VERSION 5.8 ;
BUSBITCHARS "[]" ;
DIVIDERCHAR "/" ;
UNITS
    DATABASE MICRONS 1000 ;
END UNITS

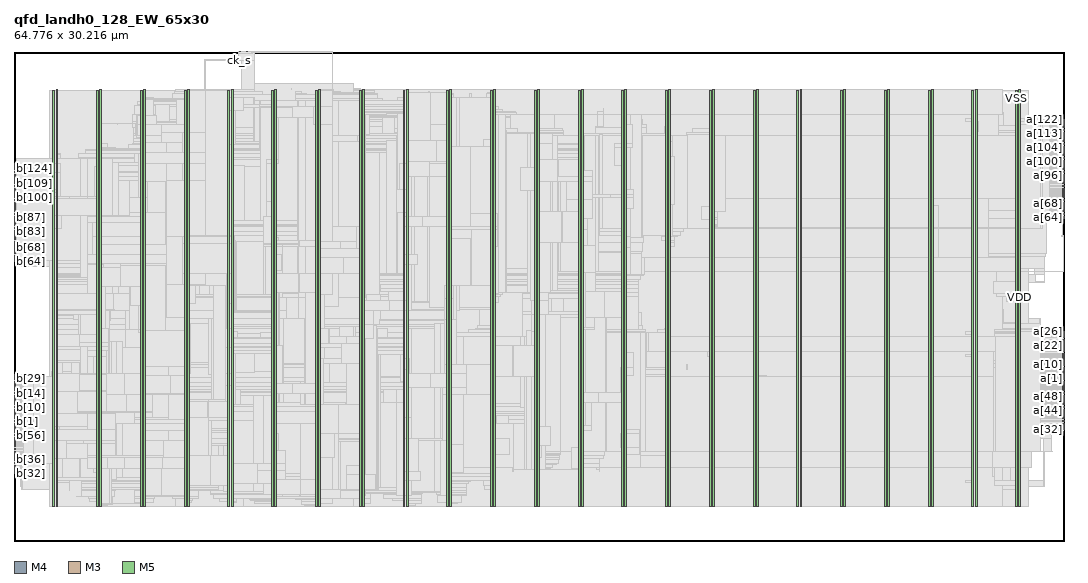
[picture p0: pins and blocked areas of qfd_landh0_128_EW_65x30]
MACRO qfd_landh0_128_EW_65x30
  FOREIGN qfd_landh0_128_EW_65x30 0 0 ;
  CLASS BLOCK ;
  SIZE 64.776 BY 30.216 ;
  PIN a[0]
    DIRECTION INPUT ;
    USE SIGNAL ;
    PORT
      LAYER M4 ;
        RECT  64.692 9.936 64.776 9.96 ;
    END
  END a[0]
  PIN a[100]
    DIRECTION INPUT ;
    USE SIGNAL ;
    PORT
      LAYER M4 ;
        RECT  64.692 23.376 64.776 23.4 ;
    END
  END a[100]
  PIN a[101]
    DIRECTION INPUT ;
    USE SIGNAL ;
    PORT
      LAYER M4 ;
        RECT  64.692 23.472 64.776 23.496 ;
    END
  END a[101]
  PIN a[102]
    DIRECTION INPUT ;
    USE SIGNAL ;
    PORT
      LAYER M4 ;
        RECT  64.692 23.568 64.776 23.592 ;
    END
  END a[102]
  PIN a[103]
    DIRECTION INPUT ;
    USE SIGNAL ;
    PORT
      LAYER M4 ;
        RECT  64.692 23.664 64.776 23.688 ;
    END
  END a[103]
  PIN a[104]
    DIRECTION INPUT ;
    USE SIGNAL ;
    PORT
      LAYER M4 ;
        RECT  64.692 23.76 64.776 23.784 ;
    END
  END a[104]
  PIN a[105]
    DIRECTION INPUT ;
    USE SIGNAL ;
    PORT
      LAYER M4 ;
        RECT  64.692 23.856 64.776 23.88 ;
    END
  END a[105]
  PIN a[106]
    DIRECTION INPUT ;
    USE SIGNAL ;
    PORT
      LAYER M4 ;
        RECT  64.692 23.952 64.776 23.976 ;
    END
  END a[106]
  PIN a[107]
    DIRECTION INPUT ;
    USE SIGNAL ;
    PORT
      LAYER M4 ;
        RECT  64.692 24.048 64.776 24.072 ;
    END
  END a[107]
  PIN a[108]
    DIRECTION INPUT ;
    USE SIGNAL ;
    PORT
      LAYER M4 ;
        RECT  64.692 24.144 64.776 24.168 ;
    END
  END a[108]
  PIN a[109]
    DIRECTION INPUT ;
    USE SIGNAL ;
    PORT
      LAYER M4 ;
        RECT  64.692 24.24 64.776 24.264 ;
    END
  END a[109]
  PIN a[10]
    DIRECTION INPUT ;
    USE SIGNAL ;
    PORT
      LAYER M4 ;
        RECT  64.692 10.896 64.776 10.92 ;
    END
  END a[10]
  PIN a[110]
    DIRECTION INPUT ;
    USE SIGNAL ;
    PORT
      LAYER M4 ;
        RECT  64.692 24.336 64.776 24.36 ;
    END
  END a[110]
  PIN a[111]
    DIRECTION INPUT ;
    USE SIGNAL ;
    PORT
      LAYER M4 ;
        RECT  64.692 24.432 64.776 24.456 ;
    END
  END a[111]
  PIN a[112]
    DIRECTION INPUT ;
    USE SIGNAL ;
    PORT
      LAYER M4 ;
        RECT  64.692 24.528 64.776 24.552 ;
    END
  END a[112]
  PIN a[113]
    DIRECTION INPUT ;
    USE SIGNAL ;
    PORT
      LAYER M4 ;
        RECT  64.692 24.624 64.776 24.648 ;
    END
  END a[113]
  PIN a[114]
    DIRECTION INPUT ;
    USE SIGNAL ;
    PORT
      LAYER M4 ;
        RECT  64.692 24.72 64.776 24.744 ;
    END
  END a[114]
  PIN a[115]
    DIRECTION INPUT ;
    USE SIGNAL ;
    PORT
      LAYER M4 ;
        RECT  64.692 24.816 64.776 24.84 ;
    END
  END a[115]
  PIN a[116]
    DIRECTION INPUT ;
    USE SIGNAL ;
    PORT
      LAYER M4 ;
        RECT  64.692 24.912 64.776 24.936 ;
    END
  END a[116]
  PIN a[117]
    DIRECTION INPUT ;
    USE SIGNAL ;
    PORT
      LAYER M4 ;
        RECT  64.692 25.008 64.776 25.032 ;
    END
  END a[117]
  PIN a[118]
    DIRECTION INPUT ;
    USE SIGNAL ;
    PORT
      LAYER M4 ;
        RECT  64.692 25.104 64.776 25.128 ;
    END
  END a[118]
  PIN a[119]
    DIRECTION INPUT ;
    USE SIGNAL ;
    PORT
      LAYER M4 ;
        RECT  64.692 25.2 64.776 25.224 ;
    END
  END a[119]
  PIN a[11]
    DIRECTION INPUT ;
    USE SIGNAL ;
    PORT
      LAYER M4 ;
        RECT  64.692 10.992 64.776 11.016 ;
    END
  END a[11]
  PIN a[120]
    DIRECTION INPUT ;
    USE SIGNAL ;
    PORT
      LAYER M4 ;
        RECT  64.692 25.296 64.776 25.32 ;
    END
  END a[120]
  PIN a[121]
    DIRECTION INPUT ;
    USE SIGNAL ;
    PORT
      LAYER M4 ;
        RECT  64.692 25.392 64.776 25.416 ;
    END
  END a[121]
  PIN a[122]
    DIRECTION INPUT ;
    USE SIGNAL ;
    PORT
      LAYER M4 ;
        RECT  64.692 25.488 64.776 25.512 ;
    END
  END a[122]
  PIN a[123]
    DIRECTION INPUT ;
    USE SIGNAL ;
    PORT
      LAYER M4 ;
        RECT  64.692 25.584 64.776 25.608 ;
    END
  END a[123]
  PIN a[124]
    DIRECTION INPUT ;
    USE SIGNAL ;
    PORT
      LAYER M4 ;
        RECT  64.692 25.68 64.776 25.704 ;
    END
  END a[124]
  PIN a[125]
    DIRECTION INPUT ;
    USE SIGNAL ;
    PORT
      LAYER M4 ;
        RECT  64.692 25.776 64.776 25.8 ;
    END
  END a[125]
  PIN a[126]
    DIRECTION INPUT ;
    USE SIGNAL ;
    PORT
      LAYER M4 ;
        RECT  64.692 25.872 64.776 25.896 ;
    END
  END a[126]
  PIN a[127]
    DIRECTION INPUT ;
    USE SIGNAL ;
    PORT
      LAYER M4 ;
        RECT  64.692 25.968 64.776 25.992 ;
    END
  END a[127]
  PIN a[12]
    DIRECTION INPUT ;
    USE SIGNAL ;
    PORT
      LAYER M4 ;
        RECT  64.692 11.088 64.776 11.112 ;
    END
  END a[12]
  PIN a[13]
    DIRECTION INPUT ;
    USE SIGNAL ;
    PORT
      LAYER M4 ;
        RECT  64.692 11.184 64.776 11.208 ;
    END
  END a[13]
  PIN a[14]
    DIRECTION INPUT ;
    USE SIGNAL ;
    PORT
      LAYER M4 ;
        RECT  64.692 11.28 64.776 11.304 ;
    END
  END a[14]
  PIN a[15]
    DIRECTION INPUT ;
    USE SIGNAL ;
    PORT
      LAYER M4 ;
        RECT  64.692 11.376 64.776 11.4 ;
    END
  END a[15]
  PIN a[16]
    DIRECTION INPUT ;
    USE SIGNAL ;
    PORT
      LAYER M4 ;
        RECT  64.692 11.472 64.776 11.496 ;
    END
  END a[16]
  PIN a[17]
    DIRECTION INPUT ;
    USE SIGNAL ;
    PORT
      LAYER M4 ;
        RECT  64.692 11.568 64.776 11.592 ;
    END
  END a[17]
  PIN a[18]
    DIRECTION INPUT ;
    USE SIGNAL ;
    PORT
      LAYER M4 ;
        RECT  64.692 11.664 64.776 11.688 ;
    END
  END a[18]
  PIN a[19]
    DIRECTION INPUT ;
    USE SIGNAL ;
    PORT
      LAYER M4 ;
        RECT  64.692 11.76 64.776 11.784 ;
    END
  END a[19]
  PIN a[1]
    DIRECTION INPUT ;
    USE SIGNAL ;
    PORT
      LAYER M4 ;
        RECT  64.692 10.032 64.776 10.056 ;
    END
  END a[1]
  PIN a[20]
    DIRECTION INPUT ;
    USE SIGNAL ;
    PORT
      LAYER M4 ;
        RECT  64.692 11.856 64.776 11.88 ;
    END
  END a[20]
  PIN a[21]
    DIRECTION INPUT ;
    USE SIGNAL ;
    PORT
      LAYER M4 ;
        RECT  64.692 11.952 64.776 11.976 ;
    END
  END a[21]
  PIN a[22]
    DIRECTION INPUT ;
    USE SIGNAL ;
    PORT
      LAYER M4 ;
        RECT  64.692 12.048 64.776 12.072 ;
    END
  END a[22]
  PIN a[23]
    DIRECTION INPUT ;
    USE SIGNAL ;
    PORT
      LAYER M4 ;
        RECT  64.692 12.144 64.776 12.168 ;
    END
  END a[23]
  PIN a[24]
    DIRECTION INPUT ;
    USE SIGNAL ;
    PORT
      LAYER M4 ;
        RECT  64.692 12.24 64.776 12.264 ;
    END
  END a[24]
  PIN a[25]
    DIRECTION INPUT ;
    USE SIGNAL ;
    PORT
      LAYER M4 ;
        RECT  64.692 12.336 64.776 12.36 ;
    END
  END a[25]
  PIN a[26]
    DIRECTION INPUT ;
    USE SIGNAL ;
    PORT
      LAYER M4 ;
        RECT  64.692 12.432 64.776 12.456 ;
    END
  END a[26]
  PIN a[27]
    DIRECTION INPUT ;
    USE SIGNAL ;
    PORT
      LAYER M4 ;
        RECT  64.692 12.528 64.776 12.552 ;
    END
  END a[27]
  PIN a[28]
    DIRECTION INPUT ;
    USE SIGNAL ;
    PORT
      LAYER M4 ;
        RECT  64.692 12.624 64.776 12.648 ;
    END
  END a[28]
  PIN a[29]
    DIRECTION INPUT ;
    USE SIGNAL ;
    PORT
      LAYER M4 ;
        RECT  64.692 12.72 64.776 12.744 ;
    END
  END a[29]
  PIN a[2]
    DIRECTION INPUT ;
    USE SIGNAL ;
    PORT
      LAYER M4 ;
        RECT  64.692 10.128 64.776 10.152 ;
    END
  END a[2]
  PIN a[30]
    DIRECTION INPUT ;
    USE SIGNAL ;
    PORT
      LAYER M4 ;
        RECT  64.692 12.816 64.776 12.84 ;
    END
  END a[30]
  PIN a[31]
    DIRECTION INPUT ;
    USE SIGNAL ;
    PORT
      LAYER M4 ;
        RECT  64.692 12.912 64.776 12.936 ;
    END
  END a[31]
  PIN a[32]
    DIRECTION INPUT ;
    USE SIGNAL ;
    PORT
      LAYER M4 ;
        RECT  64.692 6.864 64.776 6.888 ;
    END
  END a[32]
  PIN a[33]
    DIRECTION INPUT ;
    USE SIGNAL ;
    PORT
      LAYER M4 ;
        RECT  64.692 6.96 64.776 6.984 ;
    END
  END a[33]
  PIN a[34]
    DIRECTION INPUT ;
    USE SIGNAL ;
    PORT
      LAYER M4 ;
        RECT  64.692 7.056 64.776 7.08 ;
    END
  END a[34]
  PIN a[35]
    DIRECTION INPUT ;
    USE SIGNAL ;
    PORT
      LAYER M4 ;
        RECT  64.692 7.152 64.776 7.176 ;
    END
  END a[35]
  PIN a[36]
    DIRECTION INPUT ;
    USE SIGNAL ;
    PORT
      LAYER M4 ;
        RECT  64.692 7.248 64.776 7.272 ;
    END
  END a[36]
  PIN a[37]
    DIRECTION INPUT ;
    USE SIGNAL ;
    PORT
      LAYER M4 ;
        RECT  64.692 7.344 64.776 7.368 ;
    END
  END a[37]
  PIN a[38]
    DIRECTION INPUT ;
    USE SIGNAL ;
    PORT
      LAYER M4 ;
        RECT  64.692 7.44 64.776 7.464 ;
    END
  END a[38]
  PIN a[39]
    DIRECTION INPUT ;
    USE SIGNAL ;
    PORT
      LAYER M4 ;
        RECT  64.692 7.536 64.776 7.56 ;
    END
  END a[39]
  PIN a[3]
    DIRECTION INPUT ;
    USE SIGNAL ;
    PORT
      LAYER M4 ;
        RECT  64.692 10.224 64.776 10.248 ;
    END
  END a[3]
  PIN a[40]
    DIRECTION INPUT ;
    USE SIGNAL ;
    PORT
      LAYER M4 ;
        RECT  64.692 7.632 64.776 7.656 ;
    END
  END a[40]
  PIN a[41]
    DIRECTION INPUT ;
    USE SIGNAL ;
    PORT
      LAYER M4 ;
        RECT  64.692 7.728 64.776 7.752 ;
    END
  END a[41]
  PIN a[42]
    DIRECTION INPUT ;
    USE SIGNAL ;
    PORT
      LAYER M4 ;
        RECT  64.692 7.824 64.776 7.848 ;
    END
  END a[42]
  PIN a[43]
    DIRECTION INPUT ;
    USE SIGNAL ;
    PORT
      LAYER M4 ;
        RECT  64.692 7.92 64.776 7.944 ;
    END
  END a[43]
  PIN a[44]
    DIRECTION INPUT ;
    USE SIGNAL ;
    PORT
      LAYER M4 ;
        RECT  64.692 8.016 64.776 8.04 ;
    END
  END a[44]
  PIN a[45]
    DIRECTION INPUT ;
    USE SIGNAL ;
    PORT
      LAYER M4 ;
        RECT  64.692 8.112 64.776 8.136 ;
    END
  END a[45]
  PIN a[46]
    DIRECTION INPUT ;
    USE SIGNAL ;
    PORT
      LAYER M4 ;
        RECT  64.692 8.208 64.776 8.232 ;
    END
  END a[46]
  PIN a[47]
    DIRECTION INPUT ;
    USE SIGNAL ;
    PORT
      LAYER M4 ;
        RECT  64.692 8.304 64.776 8.328 ;
    END
  END a[47]
  PIN a[48]
    DIRECTION INPUT ;
    USE SIGNAL ;
    PORT
      LAYER M4 ;
        RECT  64.692 8.4 64.776 8.424 ;
    END
  END a[48]
  PIN a[49]
    DIRECTION INPUT ;
    USE SIGNAL ;
    PORT
      LAYER M4 ;
        RECT  64.692 8.496 64.776 8.52 ;
    END
  END a[49]
  PIN a[4]
    DIRECTION INPUT ;
    USE SIGNAL ;
    PORT
      LAYER M4 ;
        RECT  64.692 10.32 64.776 10.344 ;
    END
  END a[4]
  PIN a[50]
    DIRECTION INPUT ;
    USE SIGNAL ;
    PORT
      LAYER M4 ;
        RECT  64.692 8.592 64.776 8.616 ;
    END
  END a[50]
  PIN a[51]
    DIRECTION INPUT ;
    USE SIGNAL ;
    PORT
      LAYER M4 ;
        RECT  64.692 8.688 64.776 8.712 ;
    END
  END a[51]
  PIN a[52]
    DIRECTION INPUT ;
    USE SIGNAL ;
    PORT
      LAYER M4 ;
        RECT  64.692 8.784 64.776 8.808 ;
    END
  END a[52]
  PIN a[53]
    DIRECTION INPUT ;
    USE SIGNAL ;
    PORT
      LAYER M4 ;
        RECT  64.692 8.88 64.776 8.904 ;
    END
  END a[53]
  PIN a[54]
    DIRECTION INPUT ;
    USE SIGNAL ;
    PORT
      LAYER M4 ;
        RECT  64.692 8.976 64.776 9 ;
    END
  END a[54]
  PIN a[55]
    DIRECTION INPUT ;
    USE SIGNAL ;
    PORT
      LAYER M4 ;
        RECT  64.692 9.072 64.776 9.096 ;
    END
  END a[55]
  PIN a[56]
    DIRECTION INPUT ;
    USE SIGNAL ;
    PORT
      LAYER M4 ;
        RECT  64.692 9.168 64.776 9.192 ;
    END
  END a[56]
  PIN a[57]
    DIRECTION INPUT ;
    USE SIGNAL ;
    PORT
      LAYER M4 ;
        RECT  64.692 9.264 64.776 9.288 ;
    END
  END a[57]
  PIN a[58]
    DIRECTION INPUT ;
    USE SIGNAL ;
    PORT
      LAYER M4 ;
        RECT  64.692 9.36 64.776 9.384 ;
    END
  END a[58]
  PIN a[59]
    DIRECTION INPUT ;
    USE SIGNAL ;
    PORT
      LAYER M4 ;
        RECT  64.692 9.456 64.776 9.48 ;
    END
  END a[59]
  PIN a[5]
    DIRECTION INPUT ;
    USE SIGNAL ;
    PORT
      LAYER M4 ;
        RECT  64.692 10.416 64.776 10.44 ;
    END
  END a[5]
  PIN a[60]
    DIRECTION INPUT ;
    USE SIGNAL ;
    PORT
      LAYER M4 ;
        RECT  64.692 9.552 64.776 9.576 ;
    END
  END a[60]
  PIN a[61]
    DIRECTION INPUT ;
    USE SIGNAL ;
    PORT
      LAYER M4 ;
        RECT  64.692 9.648 64.776 9.672 ;
    END
  END a[61]
  PIN a[62]
    DIRECTION INPUT ;
    USE SIGNAL ;
    PORT
      LAYER M4 ;
        RECT  64.692 9.744 64.776 9.768 ;
    END
  END a[62]
  PIN a[63]
    DIRECTION INPUT ;
    USE SIGNAL ;
    PORT
      LAYER M4 ;
        RECT  64.692 9.84 64.776 9.864 ;
    END
  END a[63]
  PIN a[64]
    DIRECTION INPUT ;
    USE SIGNAL ;
    PORT
      LAYER M4 ;
        RECT  64.692 19.92 64.776 19.944 ;
    END
  END a[64]
  PIN a[65]
    DIRECTION INPUT ;
    USE SIGNAL ;
    PORT
      LAYER M4 ;
        RECT  64.692 20.016 64.776 20.04 ;
    END
  END a[65]
  PIN a[66]
    DIRECTION INPUT ;
    USE SIGNAL ;
    PORT
      LAYER M4 ;
        RECT  64.692 20.112 64.776 20.136 ;
    END
  END a[66]
  PIN a[67]
    DIRECTION INPUT ;
    USE SIGNAL ;
    PORT
      LAYER M4 ;
        RECT  64.692 20.208 64.776 20.232 ;
    END
  END a[67]
  PIN a[68]
    DIRECTION INPUT ;
    USE SIGNAL ;
    PORT
      LAYER M4 ;
        RECT  64.692 20.304 64.776 20.328 ;
    END
  END a[68]
  PIN a[69]
    DIRECTION INPUT ;
    USE SIGNAL ;
    PORT
      LAYER M4 ;
        RECT  64.692 20.4 64.776 20.424 ;
    END
  END a[69]
  PIN a[6]
    DIRECTION INPUT ;
    USE SIGNAL ;
    PORT
      LAYER M4 ;
        RECT  64.692 10.512 64.776 10.536 ;
    END
  END a[6]
  PIN a[70]
    DIRECTION INPUT ;
    USE SIGNAL ;
    PORT
      LAYER M4 ;
        RECT  64.692 20.496 64.776 20.52 ;
    END
  END a[70]
  PIN a[71]
    DIRECTION INPUT ;
    USE SIGNAL ;
    PORT
      LAYER M4 ;
        RECT  64.692 20.592 64.776 20.616 ;
    END
  END a[71]
  PIN a[72]
    DIRECTION INPUT ;
    USE SIGNAL ;
    PORT
      LAYER M4 ;
        RECT  64.692 20.688 64.776 20.712 ;
    END
  END a[72]
  PIN a[73]
    DIRECTION INPUT ;
    USE SIGNAL ;
    PORT
      LAYER M4 ;
        RECT  64.692 20.784 64.776 20.808 ;
    END
  END a[73]
  PIN a[74]
    DIRECTION INPUT ;
    USE SIGNAL ;
    PORT
      LAYER M4 ;
        RECT  64.692 20.88 64.776 20.904 ;
    END
  END a[74]
  PIN a[75]
    DIRECTION INPUT ;
    USE SIGNAL ;
    PORT
      LAYER M4 ;
        RECT  64.692 20.976 64.776 21 ;
    END
  END a[75]
  PIN a[76]
    DIRECTION INPUT ;
    USE SIGNAL ;
    PORT
      LAYER M4 ;
        RECT  64.692 21.072 64.776 21.096 ;
    END
  END a[76]
  PIN a[77]
    DIRECTION INPUT ;
    USE SIGNAL ;
    PORT
      LAYER M4 ;
        RECT  64.692 21.168 64.776 21.192 ;
    END
  END a[77]
  PIN a[78]
    DIRECTION INPUT ;
    USE SIGNAL ;
    PORT
      LAYER M4 ;
        RECT  64.692 21.264 64.776 21.288 ;
    END
  END a[78]
  PIN a[79]
    DIRECTION INPUT ;
    USE SIGNAL ;
    PORT
      LAYER M4 ;
        RECT  64.692 21.36 64.776 21.384 ;
    END
  END a[79]
  PIN a[7]
    DIRECTION INPUT ;
    USE SIGNAL ;
    PORT
      LAYER M4 ;
        RECT  64.692 10.608 64.776 10.632 ;
    END
  END a[7]
  PIN a[80]
    DIRECTION INPUT ;
    USE SIGNAL ;
    PORT
      LAYER M4 ;
        RECT  64.692 21.456 64.776 21.48 ;
    END
  END a[80]
  PIN a[81]
    DIRECTION INPUT ;
    USE SIGNAL ;
    PORT
      LAYER M4 ;
        RECT  64.692 21.552 64.776 21.576 ;
    END
  END a[81]
  PIN a[82]
    DIRECTION INPUT ;
    USE SIGNAL ;
    PORT
      LAYER M4 ;
        RECT  64.692 21.648 64.776 21.672 ;
    END
  END a[82]
  PIN a[83]
    DIRECTION INPUT ;
    USE SIGNAL ;
    PORT
      LAYER M4 ;
        RECT  64.692 21.744 64.776 21.768 ;
    END
  END a[83]
  PIN a[84]
    DIRECTION INPUT ;
    USE SIGNAL ;
    PORT
      LAYER M4 ;
        RECT  64.692 21.84 64.776 21.864 ;
    END
  END a[84]
  PIN a[85]
    DIRECTION INPUT ;
    USE SIGNAL ;
    PORT
      LAYER M4 ;
        RECT  64.692 21.936 64.776 21.96 ;
    END
  END a[85]
  PIN a[86]
    DIRECTION INPUT ;
    USE SIGNAL ;
    PORT
      LAYER M4 ;
        RECT  64.692 22.032 64.776 22.056 ;
    END
  END a[86]
  PIN a[87]
    DIRECTION INPUT ;
    USE SIGNAL ;
    PORT
      LAYER M4 ;
        RECT  64.692 22.128 64.776 22.152 ;
    END
  END a[87]
  PIN a[88]
    DIRECTION INPUT ;
    USE SIGNAL ;
    PORT
      LAYER M4 ;
        RECT  64.692 22.224 64.776 22.248 ;
    END
  END a[88]
  PIN a[89]
    DIRECTION INPUT ;
    USE SIGNAL ;
    PORT
      LAYER M4 ;
        RECT  64.692 22.32 64.776 22.344 ;
    END
  END a[89]
  PIN a[8]
    DIRECTION INPUT ;
    USE SIGNAL ;
    PORT
      LAYER M4 ;
        RECT  64.692 10.704 64.776 10.728 ;
    END
  END a[8]
  PIN a[90]
    DIRECTION INPUT ;
    USE SIGNAL ;
    PORT
      LAYER M4 ;
        RECT  64.692 22.416 64.776 22.44 ;
    END
  END a[90]
  PIN a[91]
    DIRECTION INPUT ;
    USE SIGNAL ;
    PORT
      LAYER M4 ;
        RECT  64.692 22.512 64.776 22.536 ;
    END
  END a[91]
  PIN a[92]
    DIRECTION INPUT ;
    USE SIGNAL ;
    PORT
      LAYER M4 ;
        RECT  64.692 22.608 64.776 22.632 ;
    END
  END a[92]
  PIN a[93]
    DIRECTION INPUT ;
    USE SIGNAL ;
    PORT
      LAYER M4 ;
        RECT  64.692 22.704 64.776 22.728 ;
    END
  END a[93]
  PIN a[94]
    DIRECTION INPUT ;
    USE SIGNAL ;
    PORT
      LAYER M4 ;
        RECT  64.692 22.8 64.776 22.824 ;
    END
  END a[94]
  PIN a[95]
    DIRECTION INPUT ;
    USE SIGNAL ;
    PORT
      LAYER M4 ;
        RECT  64.692 22.896 64.776 22.92 ;
    END
  END a[95]
  PIN a[96]
    DIRECTION INPUT ;
    USE SIGNAL ;
    PORT
      LAYER M4 ;
        RECT  64.692 22.992 64.776 23.016 ;
    END
  END a[96]
  PIN a[97]
    DIRECTION INPUT ;
    USE SIGNAL ;
    PORT
      LAYER M4 ;
        RECT  64.692 23.088 64.776 23.112 ;
    END
  END a[97]
  PIN a[98]
    DIRECTION INPUT ;
    USE SIGNAL ;
    PORT
      LAYER M4 ;
        RECT  64.692 23.184 64.776 23.208 ;
    END
  END a[98]
  PIN a[99]
    DIRECTION INPUT ;
    USE SIGNAL ;
    PORT
      LAYER M4 ;
        RECT  64.692 23.28 64.776 23.304 ;
    END
  END a[99]
  PIN a[9]
    DIRECTION INPUT ;
    USE SIGNAL ;
    PORT
      LAYER M4 ;
        RECT  64.692 10.8 64.776 10.824 ;
    END
  END a[9]
  PIN b[0]
    DIRECTION OUTPUT ;
    USE SIGNAL ;
    PORT
      LAYER M4 ;
        RECT  0 7.248 0.084 7.272 ;
    END
  END b[0]
  PIN b[100]
    DIRECTION OUTPUT ;
    USE SIGNAL ;
    PORT
      LAYER M4 ;
        RECT  0 20.688 0.084 20.712 ;
    END
  END b[100]
  PIN b[101]
    DIRECTION OUTPUT ;
    USE SIGNAL ;
    PORT
      LAYER M4 ;
        RECT  0 20.784 0.084 20.808 ;
    END
  END b[101]
  PIN b[102]
    DIRECTION OUTPUT ;
    USE SIGNAL ;
    PORT
      LAYER M4 ;
        RECT  0 20.88 0.084 20.904 ;
    END
  END b[102]
  PIN b[103]
    DIRECTION OUTPUT ;
    USE SIGNAL ;
    PORT
      LAYER M4 ;
        RECT  0 20.976 0.084 21 ;
    END
  END b[103]
  PIN b[104]
    DIRECTION OUTPUT ;
    USE SIGNAL ;
    PORT
      LAYER M4 ;
        RECT  0 21.072 0.084 21.096 ;
    END
  END b[104]
  PIN b[105]
    DIRECTION OUTPUT ;
    USE SIGNAL ;
    PORT
      LAYER M4 ;
        RECT  0 21.168 0.084 21.192 ;
    END
  END b[105]
  PIN b[106]
    DIRECTION OUTPUT ;
    USE SIGNAL ;
    PORT
      LAYER M4 ;
        RECT  0 21.264 0.084 21.288 ;
    END
  END b[106]
  PIN b[107]
    DIRECTION OUTPUT ;
    USE SIGNAL ;
    PORT
      LAYER M4 ;
        RECT  0 21.36 0.084 21.384 ;
    END
  END b[107]
  PIN b[108]
    DIRECTION OUTPUT ;
    USE SIGNAL ;
    PORT
      LAYER M4 ;
        RECT  0 21.456 0.084 21.48 ;
    END
  END b[108]
  PIN b[109]
    DIRECTION OUTPUT ;
    USE SIGNAL ;
    PORT
      LAYER M4 ;
        RECT  0 21.552 0.084 21.576 ;
    END
  END b[109]
  PIN b[10]
    DIRECTION OUTPUT ;
    USE SIGNAL ;
    PORT
      LAYER M4 ;
        RECT  0 8.208 0.084 8.232 ;
    END
  END b[10]
  PIN b[110]
    DIRECTION OUTPUT ;
    USE SIGNAL ;
    PORT
      LAYER M4 ;
        RECT  0 21.648 0.084 21.672 ;
    END
  END b[110]
  PIN b[111]
    DIRECTION OUTPUT ;
    USE SIGNAL ;
    PORT
      LAYER M4 ;
        RECT  0 21.744 0.084 21.768 ;
    END
  END b[111]
  PIN b[112]
    DIRECTION OUTPUT ;
    USE SIGNAL ;
    PORT
      LAYER M4 ;
        RECT  0 21.84 0.084 21.864 ;
    END
  END b[112]
  PIN b[113]
    DIRECTION OUTPUT ;
    USE SIGNAL ;
    PORT
      LAYER M4 ;
        RECT  0 21.936 0.084 21.96 ;
    END
  END b[113]
  PIN b[114]
    DIRECTION OUTPUT ;
    USE SIGNAL ;
    PORT
      LAYER M4 ;
        RECT  0 22.032 0.084 22.056 ;
    END
  END b[114]
  PIN b[115]
    DIRECTION OUTPUT ;
    USE SIGNAL ;
    PORT
      LAYER M4 ;
        RECT  0 22.128 0.084 22.152 ;
    END
  END b[115]
  PIN b[116]
    DIRECTION OUTPUT ;
    USE SIGNAL ;
    PORT
      LAYER M4 ;
        RECT  0 22.224 0.084 22.248 ;
    END
  END b[116]
  PIN b[117]
    DIRECTION OUTPUT ;
    USE SIGNAL ;
    PORT
      LAYER M4 ;
        RECT  0 22.32 0.084 22.344 ;
    END
  END b[117]
  PIN b[118]
    DIRECTION OUTPUT ;
    USE SIGNAL ;
    PORT
      LAYER M4 ;
        RECT  0 22.416 0.084 22.44 ;
    END
  END b[118]
  PIN b[119]
    DIRECTION OUTPUT ;
    USE SIGNAL ;
    PORT
      LAYER M4 ;
        RECT  0 22.512 0.084 22.536 ;
    END
  END b[119]
  PIN b[11]
    DIRECTION OUTPUT ;
    USE SIGNAL ;
    PORT
      LAYER M4 ;
        RECT  0 8.304 0.084 8.328 ;
    END
  END b[11]
  PIN b[120]
    DIRECTION OUTPUT ;
    USE SIGNAL ;
    PORT
      LAYER M4 ;
        RECT  0 22.608 0.084 22.632 ;
    END
  END b[120]
  PIN b[121]
    DIRECTION OUTPUT ;
    USE SIGNAL ;
    PORT
      LAYER M4 ;
        RECT  0 22.704 0.084 22.728 ;
    END
  END b[121]
  PIN b[122]
    DIRECTION OUTPUT ;
    USE SIGNAL ;
    PORT
      LAYER M4 ;
        RECT  0 22.8 0.084 22.824 ;
    END
  END b[122]
  PIN b[123]
    DIRECTION OUTPUT ;
    USE SIGNAL ;
    PORT
      LAYER M4 ;
        RECT  0 22.896 0.084 22.92 ;
    END
  END b[123]
  PIN b[124]
    DIRECTION OUTPUT ;
    USE SIGNAL ;
    PORT
      LAYER M4 ;
        RECT  0 22.992 0.084 23.016 ;
    END
  END b[124]
  PIN b[125]
    DIRECTION OUTPUT ;
    USE SIGNAL ;
    PORT
      LAYER M4 ;
        RECT  0 23.088 0.084 23.112 ;
    END
  END b[125]
  PIN b[126]
    DIRECTION OUTPUT ;
    USE SIGNAL ;
    PORT
      LAYER M4 ;
        RECT  0 23.184 0.084 23.208 ;
    END
  END b[126]
  PIN b[127]
    DIRECTION OUTPUT ;
    USE SIGNAL ;
    PORT
      LAYER M4 ;
        RECT  0 23.28 0.084 23.304 ;
    END
  END b[127]
  PIN b[12]
    DIRECTION OUTPUT ;
    USE SIGNAL ;
    PORT
      LAYER M4 ;
        RECT  0 8.4 0.084 8.424 ;
    END
  END b[12]
  PIN b[13]
    DIRECTION OUTPUT ;
    USE SIGNAL ;
    PORT
      LAYER M4 ;
        RECT  0 8.496 0.084 8.52 ;
    END
  END b[13]
  PIN b[14]
    DIRECTION OUTPUT ;
    USE SIGNAL ;
    PORT
      LAYER M4 ;
        RECT  0 8.592 0.084 8.616 ;
    END
  END b[14]
  PIN b[15]
    DIRECTION OUTPUT ;
    USE SIGNAL ;
    PORT
      LAYER M4 ;
        RECT  0 8.688 0.084 8.712 ;
    END
  END b[15]
  PIN b[16]
    DIRECTION OUTPUT ;
    USE SIGNAL ;
    PORT
      LAYER M4 ;
        RECT  0 8.784 0.084 8.808 ;
    END
  END b[16]
  PIN b[17]
    DIRECTION OUTPUT ;
    USE SIGNAL ;
    PORT
      LAYER M4 ;
        RECT  0 8.88 0.084 8.904 ;
    END
  END b[17]
  PIN b[18]
    DIRECTION OUTPUT ;
    USE SIGNAL ;
    PORT
      LAYER M4 ;
        RECT  0 8.976 0.084 9 ;
    END
  END b[18]
  PIN b[19]
    DIRECTION OUTPUT ;
    USE SIGNAL ;
    PORT
      LAYER M4 ;
        RECT  0 9.072 0.084 9.096 ;
    END
  END b[19]
  PIN b[1]
    DIRECTION OUTPUT ;
    USE SIGNAL ;
    PORT
      LAYER M4 ;
        RECT  0 7.344 0.084 7.368 ;
    END
  END b[1]
  PIN b[20]
    DIRECTION OUTPUT ;
    USE SIGNAL ;
    PORT
      LAYER M4 ;
        RECT  0 9.168 0.084 9.192 ;
    END
  END b[20]
  PIN b[21]
    DIRECTION OUTPUT ;
    USE SIGNAL ;
    PORT
      LAYER M4 ;
        RECT  0 9.264 0.084 9.288 ;
    END
  END b[21]
  PIN b[22]
    DIRECTION OUTPUT ;
    USE SIGNAL ;
    PORT
      LAYER M4 ;
        RECT  0 9.36 0.084 9.384 ;
    END
  END b[22]
  PIN b[23]
    DIRECTION OUTPUT ;
    USE SIGNAL ;
    PORT
      LAYER M4 ;
        RECT  0 9.456 0.084 9.48 ;
    END
  END b[23]
  PIN b[24]
    DIRECTION OUTPUT ;
    USE SIGNAL ;
    PORT
      LAYER M4 ;
        RECT  0 9.552 0.084 9.576 ;
    END
  END b[24]
  PIN b[25]
    DIRECTION OUTPUT ;
    USE SIGNAL ;
    PORT
      LAYER M4 ;
        RECT  0 9.648 0.084 9.672 ;
    END
  END b[25]
  PIN b[26]
    DIRECTION OUTPUT ;
    USE SIGNAL ;
    PORT
      LAYER M4 ;
        RECT  0 9.744 0.084 9.768 ;
    END
  END b[26]
  PIN b[27]
    DIRECTION OUTPUT ;
    USE SIGNAL ;
    PORT
      LAYER M4 ;
        RECT  0 9.84 0.084 9.864 ;
    END
  END b[27]
  PIN b[28]
    DIRECTION OUTPUT ;
    USE SIGNAL ;
    PORT
      LAYER M4 ;
        RECT  0 9.936 0.084 9.96 ;
    END
  END b[28]
  PIN b[29]
    DIRECTION OUTPUT ;
    USE SIGNAL ;
    PORT
      LAYER M4 ;
        RECT  0 10.032 0.084 10.056 ;
    END
  END b[29]
  PIN b[2]
    DIRECTION OUTPUT ;
    USE SIGNAL ;
    PORT
      LAYER M4 ;
        RECT  0 7.44 0.084 7.464 ;
    END
  END b[2]
  PIN b[30]
    DIRECTION OUTPUT ;
    USE SIGNAL ;
    PORT
      LAYER M4 ;
        RECT  0 10.128 0.084 10.152 ;
    END
  END b[30]
  PIN b[31]
    DIRECTION OUTPUT ;
    USE SIGNAL ;
    PORT
      LAYER M4 ;
        RECT  0 10.224 0.084 10.248 ;
    END
  END b[31]
  PIN b[32]
    DIRECTION OUTPUT ;
    USE SIGNAL ;
    PORT
      LAYER M4 ;
        RECT  0 4.176 0.084 4.2 ;
    END
  END b[32]
  PIN b[33]
    DIRECTION OUTPUT ;
    USE SIGNAL ;
    PORT
      LAYER M4 ;
        RECT  0 4.272 0.084 4.296 ;
    END
  END b[33]
  PIN b[34]
    DIRECTION OUTPUT ;
    USE SIGNAL ;
    PORT
      LAYER M4 ;
        RECT  0 4.368 0.084 4.392 ;
    END
  END b[34]
  PIN b[35]
    DIRECTION OUTPUT ;
    USE SIGNAL ;
    PORT
      LAYER M4 ;
        RECT  0 4.464 0.084 4.488 ;
    END
  END b[35]
  PIN b[36]
    DIRECTION OUTPUT ;
    USE SIGNAL ;
    PORT
      LAYER M4 ;
        RECT  0 4.56 0.084 4.584 ;
    END
  END b[36]
  PIN b[37]
    DIRECTION OUTPUT ;
    USE SIGNAL ;
    PORT
      LAYER M4 ;
        RECT  0 4.656 0.084 4.68 ;
    END
  END b[37]
  PIN b[38]
    DIRECTION OUTPUT ;
    USE SIGNAL ;
    PORT
      LAYER M4 ;
        RECT  0 4.752 0.084 4.776 ;
    END
  END b[38]
  PIN b[39]
    DIRECTION OUTPUT ;
    USE SIGNAL ;
    PORT
      LAYER M4 ;
        RECT  0 4.848 0.084 4.872 ;
    END
  END b[39]
  PIN b[3]
    DIRECTION OUTPUT ;
    USE SIGNAL ;
    PORT
      LAYER M4 ;
        RECT  0 7.536 0.084 7.56 ;
    END
  END b[3]
  PIN b[40]
    DIRECTION OUTPUT ;
    USE SIGNAL ;
    PORT
      LAYER M4 ;
        RECT  0 4.944 0.084 4.968 ;
    END
  END b[40]
  PIN b[41]
    DIRECTION OUTPUT ;
    USE SIGNAL ;
    PORT
      LAYER M4 ;
        RECT  0 5.04 0.084 5.064 ;
    END
  END b[41]
  PIN b[42]
    DIRECTION OUTPUT ;
    USE SIGNAL ;
    PORT
      LAYER M4 ;
        RECT  0 5.136 0.084 5.16 ;
    END
  END b[42]
  PIN b[43]
    DIRECTION OUTPUT ;
    USE SIGNAL ;
    PORT
      LAYER M4 ;
        RECT  0 5.232 0.084 5.256 ;
    END
  END b[43]
  PIN b[44]
    DIRECTION OUTPUT ;
    USE SIGNAL ;
    PORT
      LAYER M4 ;
        RECT  0 5.328 0.084 5.352 ;
    END
  END b[44]
  PIN b[45]
    DIRECTION OUTPUT ;
    USE SIGNAL ;
    PORT
      LAYER M4 ;
        RECT  0 5.424 0.084 5.448 ;
    END
  END b[45]
  PIN b[46]
    DIRECTION OUTPUT ;
    USE SIGNAL ;
    PORT
      LAYER M4 ;
        RECT  0 5.52 0.084 5.544 ;
    END
  END b[46]
  PIN b[47]
    DIRECTION OUTPUT ;
    USE SIGNAL ;
    PORT
      LAYER M4 ;
        RECT  0 5.616 0.084 5.64 ;
    END
  END b[47]
  PIN b[48]
    DIRECTION OUTPUT ;
    USE SIGNAL ;
    PORT
      LAYER M4 ;
        RECT  0 5.712 0.084 5.736 ;
    END
  END b[48]
  PIN b[49]
    DIRECTION OUTPUT ;
    USE SIGNAL ;
    PORT
      LAYER M4 ;
        RECT  0 5.808 0.084 5.832 ;
    END
  END b[49]
  PIN b[4]
    DIRECTION OUTPUT ;
    USE SIGNAL ;
    PORT
      LAYER M4 ;
        RECT  0 7.632 0.084 7.656 ;
    END
  END b[4]
  PIN b[50]
    DIRECTION OUTPUT ;
    USE SIGNAL ;
    PORT
      LAYER M4 ;
        RECT  0 5.904 0.084 5.928 ;
    END
  END b[50]
  PIN b[51]
    DIRECTION OUTPUT ;
    USE SIGNAL ;
    PORT
      LAYER M4 ;
        RECT  0 6 0.084 6.024 ;
    END
  END b[51]
  PIN b[52]
    DIRECTION OUTPUT ;
    USE SIGNAL ;
    PORT
      LAYER M4 ;
        RECT  0 6.096 0.084 6.12 ;
    END
  END b[52]
  PIN b[53]
    DIRECTION OUTPUT ;
    USE SIGNAL ;
    PORT
      LAYER M4 ;
        RECT  0 6.192 0.084 6.216 ;
    END
  END b[53]
  PIN b[54]
    DIRECTION OUTPUT ;
    USE SIGNAL ;
    PORT
      LAYER M4 ;
        RECT  0 6.288 0.084 6.312 ;
    END
  END b[54]
  PIN b[55]
    DIRECTION OUTPUT ;
    USE SIGNAL ;
    PORT
      LAYER M4 ;
        RECT  0 6.384 0.084 6.408 ;
    END
  END b[55]
  PIN b[56]
    DIRECTION OUTPUT ;
    USE SIGNAL ;
    PORT
      LAYER M4 ;
        RECT  0 6.48 0.084 6.504 ;
    END
  END b[56]
  PIN b[57]
    DIRECTION OUTPUT ;
    USE SIGNAL ;
    PORT
      LAYER M4 ;
        RECT  0 6.576 0.084 6.6 ;
    END
  END b[57]
  PIN b[58]
    DIRECTION OUTPUT ;
    USE SIGNAL ;
    PORT
      LAYER M4 ;
        RECT  0 6.672 0.084 6.696 ;
    END
  END b[58]
  PIN b[59]
    DIRECTION OUTPUT ;
    USE SIGNAL ;
    PORT
      LAYER M4 ;
        RECT  0 6.768 0.084 6.792 ;
    END
  END b[59]
  PIN b[5]
    DIRECTION OUTPUT ;
    USE SIGNAL ;
    PORT
      LAYER M4 ;
        RECT  0 7.728 0.084 7.752 ;
    END
  END b[5]
  PIN b[60]
    DIRECTION OUTPUT ;
    USE SIGNAL ;
    PORT
      LAYER M4 ;
        RECT  0 6.864 0.084 6.888 ;
    END
  END b[60]
  PIN b[61]
    DIRECTION OUTPUT ;
    USE SIGNAL ;
    PORT
      LAYER M4 ;
        RECT  0 6.96 0.084 6.984 ;
    END
  END b[61]
  PIN b[62]
    DIRECTION OUTPUT ;
    USE SIGNAL ;
    PORT
      LAYER M4 ;
        RECT  0 7.056 0.084 7.08 ;
    END
  END b[62]
  PIN b[63]
    DIRECTION OUTPUT ;
    USE SIGNAL ;
    PORT
      LAYER M4 ;
        RECT  0 7.152 0.084 7.176 ;
    END
  END b[63]
  PIN b[64]
    DIRECTION OUTPUT ;
    USE SIGNAL ;
    PORT
      LAYER M4 ;
        RECT  0 17.232 0.084 17.256 ;
    END
  END b[64]
  PIN b[65]
    DIRECTION OUTPUT ;
    USE SIGNAL ;
    PORT
      LAYER M4 ;
        RECT  0 17.328 0.084 17.352 ;
    END
  END b[65]
  PIN b[66]
    DIRECTION OUTPUT ;
    USE SIGNAL ;
    PORT
      LAYER M4 ;
        RECT  0 17.424 0.084 17.448 ;
    END
  END b[66]
  PIN b[67]
    DIRECTION OUTPUT ;
    USE SIGNAL ;
    PORT
      LAYER M4 ;
        RECT  0 17.52 0.084 17.544 ;
    END
  END b[67]
  PIN b[68]
    DIRECTION OUTPUT ;
    USE SIGNAL ;
    PORT
      LAYER M4 ;
        RECT  0 17.616 0.084 17.64 ;
    END
  END b[68]
  PIN b[69]
    DIRECTION OUTPUT ;
    USE SIGNAL ;
    PORT
      LAYER M4 ;
        RECT  0 17.712 0.084 17.736 ;
    END
  END b[69]
  PIN b[6]
    DIRECTION OUTPUT ;
    USE SIGNAL ;
    PORT
      LAYER M4 ;
        RECT  0 7.824 0.084 7.848 ;
    END
  END b[6]
  PIN b[70]
    DIRECTION OUTPUT ;
    USE SIGNAL ;
    PORT
      LAYER M4 ;
        RECT  0 17.808 0.084 17.832 ;
    END
  END b[70]
  PIN b[71]
    DIRECTION OUTPUT ;
    USE SIGNAL ;
    PORT
      LAYER M4 ;
        RECT  0 17.904 0.084 17.928 ;
    END
  END b[71]
  PIN b[72]
    DIRECTION OUTPUT ;
    USE SIGNAL ;
    PORT
      LAYER M4 ;
        RECT  0 18 0.084 18.024 ;
    END
  END b[72]
  PIN b[73]
    DIRECTION OUTPUT ;
    USE SIGNAL ;
    PORT
      LAYER M4 ;
        RECT  0 18.096 0.084 18.12 ;
    END
  END b[73]
  PIN b[74]
    DIRECTION OUTPUT ;
    USE SIGNAL ;
    PORT
      LAYER M4 ;
        RECT  0 18.192 0.084 18.216 ;
    END
  END b[74]
  PIN b[75]
    DIRECTION OUTPUT ;
    USE SIGNAL ;
    PORT
      LAYER M4 ;
        RECT  0 18.288 0.084 18.312 ;
    END
  END b[75]
  PIN b[76]
    DIRECTION OUTPUT ;
    USE SIGNAL ;
    PORT
      LAYER M4 ;
        RECT  0 18.384 0.084 18.408 ;
    END
  END b[76]
  PIN b[77]
    DIRECTION OUTPUT ;
    USE SIGNAL ;
    PORT
      LAYER M4 ;
        RECT  0 18.48 0.084 18.504 ;
    END
  END b[77]
  PIN b[78]
    DIRECTION OUTPUT ;
    USE SIGNAL ;
    PORT
      LAYER M4 ;
        RECT  0 18.576 0.084 18.6 ;
    END
  END b[78]
  PIN b[79]
    DIRECTION OUTPUT ;
    USE SIGNAL ;
    PORT
      LAYER M4 ;
        RECT  0 18.672 0.084 18.696 ;
    END
  END b[79]
  PIN b[7]
    DIRECTION OUTPUT ;
    USE SIGNAL ;
    PORT
      LAYER M4 ;
        RECT  0 7.92 0.084 7.944 ;
    END
  END b[7]
  PIN b[80]
    DIRECTION OUTPUT ;
    USE SIGNAL ;
    PORT
      LAYER M4 ;
        RECT  0 18.768 0.084 18.792 ;
    END
  END b[80]
  PIN b[81]
    DIRECTION OUTPUT ;
    USE SIGNAL ;
    PORT
      LAYER M4 ;
        RECT  0 18.864 0.084 18.888 ;
    END
  END b[81]
  PIN b[82]
    DIRECTION OUTPUT ;
    USE SIGNAL ;
    PORT
      LAYER M4 ;
        RECT  0 18.96 0.084 18.984 ;
    END
  END b[82]
  PIN b[83]
    DIRECTION OUTPUT ;
    USE SIGNAL ;
    PORT
      LAYER M4 ;
        RECT  0 19.056 0.084 19.08 ;
    END
  END b[83]
  PIN b[84]
    DIRECTION OUTPUT ;
    USE SIGNAL ;
    PORT
      LAYER M4 ;
        RECT  0 19.152 0.084 19.176 ;
    END
  END b[84]
  PIN b[85]
    DIRECTION OUTPUT ;
    USE SIGNAL ;
    PORT
      LAYER M4 ;
        RECT  0 19.248 0.084 19.272 ;
    END
  END b[85]
  PIN b[86]
    DIRECTION OUTPUT ;
    USE SIGNAL ;
    PORT
      LAYER M4 ;
        RECT  0 19.344 0.084 19.368 ;
    END
  END b[86]
  PIN b[87]
    DIRECTION OUTPUT ;
    USE SIGNAL ;
    PORT
      LAYER M4 ;
        RECT  0 19.44 0.084 19.464 ;
    END
  END b[87]
  PIN b[88]
    DIRECTION OUTPUT ;
    USE SIGNAL ;
    PORT
      LAYER M4 ;
        RECT  0 19.536 0.084 19.56 ;
    END
  END b[88]
  PIN b[89]
    DIRECTION OUTPUT ;
    USE SIGNAL ;
    PORT
      LAYER M4 ;
        RECT  0 19.632 0.084 19.656 ;
    END
  END b[89]
  PIN b[8]
    DIRECTION OUTPUT ;
    USE SIGNAL ;
    PORT
      LAYER M4 ;
        RECT  0 8.016 0.084 8.04 ;
    END
  END b[8]
  PIN b[90]
    DIRECTION OUTPUT ;
    USE SIGNAL ;
    PORT
      LAYER M4 ;
        RECT  0 19.728 0.084 19.752 ;
    END
  END b[90]
  PIN b[91]
    DIRECTION OUTPUT ;
    USE SIGNAL ;
    PORT
      LAYER M4 ;
        RECT  0 19.824 0.084 19.848 ;
    END
  END b[91]
  PIN b[92]
    DIRECTION OUTPUT ;
    USE SIGNAL ;
    PORT
      LAYER M4 ;
        RECT  0 19.92 0.084 19.944 ;
    END
  END b[92]
  PIN b[93]
    DIRECTION OUTPUT ;
    USE SIGNAL ;
    PORT
      LAYER M4 ;
        RECT  0 20.016 0.084 20.04 ;
    END
  END b[93]
  PIN b[94]
    DIRECTION OUTPUT ;
    USE SIGNAL ;
    PORT
      LAYER M4 ;
        RECT  0 20.112 0.084 20.136 ;
    END
  END b[94]
  PIN b[95]
    DIRECTION OUTPUT ;
    USE SIGNAL ;
    PORT
      LAYER M4 ;
        RECT  0 20.208 0.084 20.232 ;
    END
  END b[95]
  PIN b[96]
    DIRECTION OUTPUT ;
    USE SIGNAL ;
    PORT
      LAYER M4 ;
        RECT  0 20.304 0.084 20.328 ;
    END
  END b[96]
  PIN b[97]
    DIRECTION OUTPUT ;
    USE SIGNAL ;
    PORT
      LAYER M4 ;
        RECT  0 20.4 0.084 20.424 ;
    END
  END b[97]
  PIN b[98]
    DIRECTION OUTPUT ;
    USE SIGNAL ;
    PORT
      LAYER M4 ;
        RECT  0 20.496 0.084 20.52 ;
    END
  END b[98]
  PIN b[99]
    DIRECTION OUTPUT ;
    USE SIGNAL ;
    PORT
      LAYER M4 ;
        RECT  0 20.592 0.084 20.616 ;
    END
  END b[99]
  PIN b[9]
    DIRECTION OUTPUT ;
    USE SIGNAL ;
    PORT
      LAYER M4 ;
        RECT  0 8.112 0.084 8.136 ;
    END
  END b[9]
  PIN ck
    DIRECTION INPUT ;
    USE SIGNAL ;
    PORT
      LAYER M3 ;
        RECT  13.86 30.179 13.878 30.216 ;
    END
  END ck
  PIN ck_s
    DIRECTION INPUT ;
    USE SIGNAL ;
    PORT
      LAYER M3 ;
        RECT  13.932 30.179 13.95 30.216 ;
    END
  END ck_s
  PIN en
    DIRECTION INPUT ;
    USE SIGNAL ;
    PORT
      LAYER M3 ;
        RECT  14.004 30.179 14.022 30.216 ;
    END
  END en
  PIN fault
    DIRECTION OUTPUT ;
    USE SIGNAL ;
    PORT
      LAYER M3 ;
        RECT  14.076 30.179 14.094 30.216 ;
    END
  END fault
  PIN k0
    DIRECTION INPUT ;
    USE SIGNAL ;
    PORT
      LAYER M3 ;
        RECT  14.148 30.179 14.166 30.216 ;
    END
  END k0
  PIN k1
    DIRECTION INPUT ;
    USE SIGNAL ;
    PORT
      LAYER M3 ;
        RECT  14.22 30.179 14.238 30.216 ;
    END
  END k1
  PIN k2
    DIRECTION INPUT ;
    USE SIGNAL ;
    PORT
      LAYER M3 ;
        RECT  14.292 30.179 14.31 30.216 ;
    END
  END k2
  PIN rs
    DIRECTION INPUT ;
    USE SIGNAL ;
    PORT
      LAYER M3 ;
        RECT  14.364 30.179 14.382 30.216 ;
    END
  END rs
  PIN tie_hi
    DIRECTION OUTPUT ;
    USE SIGNAL ;
    PORT
      LAYER M3 ;
        RECT  14.436 30.179 14.454 30.216 ;
    END
  END tie_hi
  PIN tie_lo
    DIRECTION OUTPUT ;
    USE SIGNAL ;
    PORT
      LAYER M3 ;
        RECT  14.508 30.179 14.526 30.216 ;
    END
  END tie_lo
  PIN VDD
    DIRECTION INOUT ;
    USE POWER ;
    PORT
      LAYER M5 ;
        RECT  61.992 2.151 62.112 27.833 ;
        RECT  59.292 2.151 59.412 27.833 ;
        RECT  56.592 2.151 56.712 27.833 ;
        RECT  53.892 2.151 54.012 27.833 ;
        RECT  51.192 2.151 51.312 27.833 ;
        RECT  48.492 2.151 48.612 27.833 ;
        RECT  45.792 2.151 45.912 27.833 ;
        RECT  43.092 2.151 43.212 27.833 ;
        RECT  40.392 2.151 40.512 27.833 ;
        RECT  37.692 2.151 37.812 27.833 ;
        RECT  34.992 2.151 35.112 27.833 ;
        RECT  32.292 2.151 32.412 27.833 ;
        RECT  29.592 2.151 29.712 27.833 ;
        RECT  26.892 2.151 27.012 27.833 ;
        RECT  24.192 2.151 24.312 27.833 ;
        RECT  21.492 2.151 21.612 27.833 ;
        RECT  18.792 2.151 18.912 27.833 ;
        RECT  16.092 2.151 16.212 27.833 ;
        RECT  13.392 2.151 13.512 27.833 ;
        RECT  10.692 2.151 10.812 27.833 ;
        RECT  7.992 2.151 8.112 27.833 ;
        RECT  5.292 2.151 5.412 27.833 ;
        RECT  2.592 2.151 2.712 27.833 ;
    END
  END VDD
  PIN VSS
    DIRECTION INOUT ;
    USE GROUND ;
    PORT
      LAYER M5 ;
        RECT  61.8 2.137 61.92 27.819 ;
        RECT  59.1 2.137 59.22 27.819 ;
        RECT  56.4 2.137 56.52 27.819 ;
        RECT  53.7 2.137 53.82 27.819 ;
        RECT  51 2.137 51.12 27.819 ;
        RECT  48.3 2.137 48.42 27.819 ;
        RECT  45.6 2.137 45.72 27.819 ;
        RECT  42.9 2.137 43.02 27.819 ;
        RECT  40.2 2.137 40.32 27.819 ;
        RECT  37.5 2.137 37.62 27.819 ;
        RECT  34.8 2.137 34.92 27.819 ;
        RECT  32.1 2.137 32.22 27.819 ;
        RECT  29.4 2.137 29.52 27.819 ;
        RECT  26.7 2.137 26.82 27.819 ;
        RECT  24 2.137 24.12 27.819 ;
        RECT  21.3 2.137 21.42 27.819 ;
        RECT  18.6 2.137 18.72 27.819 ;
        RECT  15.9 2.137 16.02 27.819 ;
        RECT  13.2 2.137 13.32 27.819 ;
        RECT  10.5 2.137 10.62 27.819 ;
        RECT  7.8 2.137 7.92 27.819 ;
        RECT  5.1 2.137 5.22 27.819 ;
        RECT  2.4 2.137 2.52 27.819 ;
    END
  END VSS
  # OT_OBS_CLOSED layer=M5 d_um=1.536 added=109
  OBS
    LAYER RVTN ;
     RECT  2.16 2.16 62.586 2.295 ;
     RECT  2.16 2.565 62.586 2.835 ;
     RECT  2.16 3.105 62.586 3.375 ;
     RECT  2.16 3.645 62.586 3.915 ;
     RECT  2.16 4.185 62.586 4.455 ;
     RECT  2.16 4.725 62.586 4.995 ;
     RECT  2.16 5.265 62.586 5.535 ;
     RECT  2.16 5.805 62.586 6.075 ;
     RECT  2.16 6.345 62.586 6.615 ;
     RECT  2.16 6.885 62.586 7.155 ;
     RECT  2.16 7.425 62.586 7.695 ;
     RECT  2.16 7.965 62.586 8.235 ;
     RECT  2.16 8.505 62.586 8.775 ;
     RECT  2.16 9.045 62.586 9.315 ;
     RECT  2.16 9.585 62.586 9.855 ;
     RECT  2.16 10.125 62.586 10.395 ;
     RECT  2.16 10.665 62.586 10.935 ;
     RECT  2.16 11.205 62.586 11.475 ;
     RECT  2.16 11.745 62.586 12.015 ;
     RECT  2.16 12.285 62.586 12.555 ;
     RECT  2.16 12.825 62.586 13.095 ;
     RECT  2.16 13.365 62.586 13.635 ;
     RECT  2.16 13.905 62.586 14.175 ;
     RECT  2.16 14.445 62.586 14.715 ;
     RECT  2.16 14.985 62.586 15.255 ;
     RECT  2.16 15.525 62.586 15.795 ;
     RECT  2.16 16.065 62.586 16.335 ;
     RECT  2.16 16.605 62.586 16.875 ;
     RECT  2.16 17.145 62.586 17.415 ;
     RECT  2.16 17.685 62.586 17.955 ;
     RECT  2.16 18.225 62.586 18.495 ;
     RECT  2.16 18.765 62.586 19.035 ;
     RECT  2.16 19.305 62.586 19.575 ;
     RECT  2.16 19.845 62.586 20.115 ;
     RECT  2.16 20.385 62.586 20.655 ;
     RECT  2.16 20.925 62.586 21.195 ;
     RECT  2.16 21.465 62.586 21.735 ;
     RECT  2.16 22.005 62.586 22.275 ;
     RECT  2.16 22.545 62.586 22.815 ;
     RECT  2.16 23.085 62.586 23.355 ;
     RECT  2.16 23.625 62.586 23.895 ;
     RECT  2.16 24.165 62.586 24.435 ;
     RECT  2.16 24.705 62.586 24.975 ;
     RECT  2.16 25.245 62.586 25.515 ;
     RECT  2.16 25.785 62.586 26.055 ;
     RECT  2.16 26.325 62.586 26.595 ;
     RECT  2.16 26.865 62.586 27.135 ;
     RECT  2.16 27.405 62.586 27.675 ;
    LAYER RVTP ;
     RECT  2.16 2.295 62.586 2.565 ;
     RECT  2.16 2.835 62.586 3.105 ;
     RECT  2.16 3.375 62.586 3.645 ;
     RECT  2.16 3.915 62.586 4.185 ;
     RECT  2.16 4.455 62.586 4.725 ;
     RECT  2.16 4.995 62.586 5.265 ;
     RECT  2.16 5.535 62.586 5.805 ;
     RECT  2.16 6.075 62.586 6.345 ;
     RECT  2.16 6.615 62.586 6.885 ;
     RECT  2.16 7.155 62.586 7.425 ;
     RECT  2.16 7.695 62.586 7.965 ;
     RECT  2.16 8.235 62.586 8.505 ;
     RECT  2.16 8.775 62.586 9.045 ;
     RECT  2.16 9.315 62.586 9.585 ;
     RECT  2.16 9.855 62.586 10.125 ;
     RECT  2.16 10.395 62.586 10.665 ;
     RECT  2.16 10.935 62.586 11.205 ;
     RECT  2.16 11.475 62.586 11.745 ;
     RECT  2.16 12.015 62.586 12.285 ;
     RECT  2.16 12.555 62.586 12.825 ;
     RECT  2.16 13.095 62.586 13.365 ;
     RECT  2.16 13.635 62.586 13.905 ;
     RECT  2.16 14.175 62.586 14.445 ;
     RECT  2.16 14.715 62.586 14.985 ;
     RECT  2.16 15.255 62.586 15.525 ;
     RECT  2.16 15.795 62.586 16.065 ;
     RECT  2.16 16.335 62.586 16.605 ;
     RECT  2.16 16.875 62.586 17.145 ;
     RECT  2.16 17.415 62.586 17.685 ;
     RECT  2.16 17.955 62.586 18.225 ;
     RECT  2.16 18.495 62.586 18.765 ;
     RECT  2.16 19.035 62.586 19.305 ;
     RECT  2.16 19.575 62.586 19.845 ;
     RECT  2.16 20.115 62.586 20.385 ;
     RECT  2.16 20.655 62.586 20.925 ;
     RECT  2.16 21.195 62.586 21.465 ;
     RECT  2.16 21.735 62.586 22.005 ;
     RECT  2.16 22.275 62.586 22.545 ;
     RECT  2.16 22.815 62.586 23.085 ;
     RECT  2.16 23.355 62.586 23.625 ;
     RECT  2.16 23.895 62.586 24.165 ;
     RECT  2.16 24.435 62.586 24.705 ;
     RECT  2.16 24.975 62.586 25.245 ;
     RECT  2.16 25.515 62.586 25.785 ;
     RECT  2.16 26.055 62.586 26.325 ;
     RECT  2.16 26.595 62.586 26.865 ;
     RECT  2.16 27.135 62.586 27.405 ;
     RECT  2.16 27.675 62.586 27.81 ;
    LAYER M1 ;
     RECT  2.16 2.151 62.586 27.819 ;
    LAYER M2 ;
     RECT  0.103 3.96 0.139 3.978 ;
     RECT  0.103 17.046 0.139 17.064 ;
     RECT  0.103 18.621 0.139 18.639 ;
     RECT  0.139 3.96 0.175 4.284 ;
     RECT  0.103 5.076 0.175 5.634 ;
     RECT  0.139 18.576 0.203 18.639 ;
     RECT  0.103 22.518 0.203 22.536 ;
     RECT  0.103 8.982 0.347 9 ;
     RECT  0.319 23.166 0.419 23.184 ;
     RECT  0.175 3.96 0.427 5.634 ;
     RECT  0.427 3.384 0.463 5.634 ;
     RECT  0.463 3.186 0.535 5.634 ;
     RECT  0.103 6.786 0.535 6.804 ;
     RECT  0.139 16.956 0.535 17.064 ;
     RECT  0.203 18.576 0.535 18.594 ;
     RECT  0.535 3.186 2.16 6.804 ;
     RECT  0.535 16.956 2.16 18.594 ;
     RECT  0.535 20.466 2.16 20.484 ;
     RECT  2.16 2.151 9.967 27.819 ;
     RECT  9.967 2.151 14.143 27.864 ;
     RECT  14.287 30.15 14.819 30.168 ;
     RECT  14.143 2.151 20.939 28.206 ;
     RECT  20.939 2.151 21.371 27.936 ;
     RECT  21.371 2.151 61.007 27.864 ;
     RECT  61.007 2.151 62.586 27.819 ;
     RECT  62.586 4.536 62.735 5.292 ;
     RECT  62.586 23.094 62.735 23.346 ;
     RECT  62.735 4.536 62.771 4.554 ;
     RECT  62.586 15.966 62.987 16.434 ;
     RECT  62.586 18.54 63.023 18.828 ;
     RECT  62.586 17.46 63.059 17.748 ;
     RECT  63.023 18.576 63.167 18.828 ;
     RECT  62.586 6.39 63.311 7.488 ;
     RECT  62.586 8.514 63.311 13.698 ;
     RECT  63.167 18.774 63.311 18.828 ;
     RECT  62.586 24.138 63.311 26.154 ;
     RECT  63.311 8.856 63.347 13.122 ;
     RECT  62.586 19.584 63.347 22.23 ;
     RECT  63.347 19.584 63.419 22.032 ;
     RECT  62.586 3.384 63.563 3.708 ;
     RECT  63.311 18.81 63.563 18.828 ;
     RECT  63.563 3.69 63.599 3.708 ;
     RECT  62.987 15.966 63.599 15.984 ;
     RECT  63.059 17.586 63.635 17.748 ;
     RECT  63.635 17.73 63.671 17.748 ;
     RECT  63.311 6.588 63.887 7.38 ;
     RECT  63.347 8.856 63.887 13.086 ;
     RECT  63.419 19.89 63.887 22.032 ;
     RECT  63.311 24.138 63.887 25.974 ;
     RECT  63.887 9.324 63.923 12.924 ;
     RECT  63.887 20.394 63.923 21.996 ;
     RECT  62.735 23.13 63.923 23.346 ;
     RECT  63.887 24.138 63.923 25.344 ;
     RECT  63.923 9.936 63.959 10.494 ;
     RECT  63.923 11.484 63.959 11.502 ;
     RECT  63.923 12.834 63.959 12.852 ;
     RECT  63.923 20.394 63.959 20.412 ;
     RECT  63.923 24.138 63.959 24.462 ;
     RECT  63.923 25.326 63.959 25.344 ;
     RECT  63.923 21.474 63.995 21.996 ;
     RECT  63.959 24.138 63.995 24.156 ;
     RECT  63.995 21.816 64.031 21.996 ;
     RECT  63.887 6.588 64.067 6.84 ;
     RECT  64.067 6.822 64.615 6.84 ;
     RECT  64.615 6.822 64.751 6.876 ;
     RECT  64.651 8.55 64.751 9.27 ;
     RECT  64.651 11.826 64.751 11.844 ;
     RECT  64.651 18.81 64.751 18.828 ;
     RECT  64.031 21.816 64.751 21.834 ;
    LAYER M3 ;
     RECT  5.115 2.143 5.205 2.191 ;
     RECT  18.615 2.143 18.705 2.191 ;
     RECT  24.015 2.143 24.105 2.191 ;
     RECT  5.115 2.191 5.742 2.227 ;
     RECT  17.928 2.191 18.705 2.263 ;
     RECT  5.115 2.227 6.102 2.299 ;
     RECT  7.815 2.143 7.905 2.299 ;
     RECT  21.315 2.143 21.405 2.299 ;
     RECT  24.015 2.191 24.786 2.299 ;
     RECT  26.715 2.143 26.805 2.299 ;
     RECT  14.832 2.299 14.85 2.335 ;
     RECT  15.915 2.143 16.005 2.335 ;
     RECT  7.416 2.299 7.905 2.371 ;
     RECT  10.515 2.143 10.605 2.371 ;
     RECT  13.215 2.143 13.305 2.371 ;
     RECT  26.715 2.299 27.378 2.371 ;
     RECT  2.415 2.143 2.505 2.413 ;
     RECT  14.832 2.335 16.005 2.413 ;
     RECT  17.748 2.263 18.705 2.413 ;
     RECT  19.512 2.299 19.638 2.413 ;
     RECT  29.415 2.143 29.505 2.413 ;
     RECT  32.115 2.143 32.205 2.413 ;
     RECT  34.815 2.143 34.905 2.413 ;
     RECT  37.515 2.143 37.605 2.413 ;
     RECT  40.215 2.143 40.305 2.413 ;
     RECT  42.915 2.143 43.005 2.413 ;
     RECT  45.615 2.143 45.705 2.413 ;
     RECT  48.315 2.143 48.405 2.413 ;
     RECT  51.015 2.143 51.105 2.413 ;
     RECT  53.715 2.143 53.805 2.413 ;
     RECT  56.415 2.143 56.505 2.413 ;
     RECT  59.115 2.143 59.205 2.413 ;
     RECT  61.815 2.143 61.905 2.413 ;
     RECT  5.076 2.299 6.102 2.461 ;
     RECT  13.215 2.371 13.698 2.461 ;
     RECT  10.515 2.371 10.926 2.497 ;
     RECT  14.832 2.413 16.197 2.497 ;
     RECT  24.015 2.299 25.11 2.497 ;
     RECT  14.616 2.497 16.197 2.533 ;
     RECT  17.748 2.413 19.638 2.569 ;
     RECT  4.644 2.461 6.102 2.605 ;
     RECT  7.416 2.371 8.622 2.605 ;
     RECT  10.515 2.497 10.998 2.605 ;
     RECT  14.544 2.533 16.197 2.605 ;
     RECT  21.315 2.299 22.014 2.605 ;
     RECT  23.364 2.497 25.11 2.605 ;
     RECT  9.792 2.605 11.106 2.641 ;
     RECT  12.708 2.461 13.698 2.641 ;
     RECT  14.544 2.605 16.254 2.641 ;
     RECT  17.352 2.569 19.638 2.641 ;
     RECT  4.608 2.605 6.102 2.725 ;
     RECT  3.888 2.725 6.102 2.731 ;
     RECT  3.888 2.731 6.21 2.765 ;
     RECT  7.416 2.605 8.694 2.767 ;
     RECT  9.792 2.641 11.394 2.767 ;
     RECT  26.136 2.371 27.63 2.827 ;
     RECT  12.312 2.641 19.818 2.839 ;
     RECT  22.824 2.605 25.11 2.875 ;
     RECT  26.136 2.827 27.918 2.875 ;
     RECT  12.132 2.839 19.818 2.911 ;
     RECT  20.988 2.605 22.014 2.911 ;
     RECT  22.824 2.875 25.146 2.911 ;
     RECT  20.988 2.911 25.218 3.019 ;
     RECT  26.064 2.875 27.918 3.019 ;
     RECT  7.416 2.767 11.394 3.109 ;
     RECT  12.132 2.911 19.998 3.109 ;
     RECT  20.988 3.019 27.918 3.115 ;
     RECT  4.176 2.765 6.21 3.145 ;
     RECT  4.176 3.145 6.246 3.181 ;
     RECT  7.416 3.109 19.998 3.181 ;
     RECT  29.415 2.413 29.697 3.181 ;
     RECT  60.984 2.641 61.002 3.181 ;
     RECT  61.815 2.413 62.097 3.181 ;
     RECT  4.176 3.181 19.998 3.271 ;
     RECT  20.772 3.115 27.918 3.271 ;
     RECT  0.468 3.181 0.486 3.379 ;
     RECT  60.984 3.181 62.097 3.415 ;
     RECT  29.052 3.181 29.697 3.451 ;
     RECT  4.176 3.271 27.918 3.541 ;
     RECT  2.415 2.413 2.697 3.613 ;
     RECT  3.42 3.145 3.438 3.613 ;
     RECT  59.115 2.413 59.397 3.613 ;
     RECT  4.176 3.541 28.026 3.685 ;
     RECT  63.54 3.379 63.558 3.685 ;
     RECT  58.716 3.613 59.397 3.713 ;
     RECT  0.432 3.379 0.486 3.721 ;
     RECT  2.415 3.613 3.438 3.721 ;
     RECT  4.176 3.685 28.134 3.721 ;
     RECT  28.98 3.451 29.697 3.721 ;
     RECT  60.48 3.415 62.097 3.749 ;
     RECT  0.432 3.721 0.558 3.955 ;
     RECT  60.48 3.749 60.498 3.955 ;
     RECT  2.415 3.721 29.697 3.983 ;
     RECT  13.215 3.983 29.697 4.145 ;
     RECT  36.108 4.261 36.126 4.387 ;
     RECT  30.78 4.261 30.798 4.411 ;
     RECT  32.115 2.413 32.397 4.495 ;
     RECT  34.815 2.413 35.097 4.507 ;
     RECT  60.336 3.955 60.498 4.507 ;
     RECT  61.488 3.749 62.097 4.507 ;
     RECT  32.115 4.495 33.102 4.531 ;
     RECT  34.776 4.507 35.097 4.531 ;
     RECT  35.964 4.387 36.126 4.531 ;
     RECT  60.336 4.507 62.097 4.531 ;
     RECT  30.78 4.411 30.834 4.657 ;
     RECT  30.78 4.657 31.374 4.693 ;
     RECT  32.115 4.531 33.21 4.693 ;
     RECT  34.776 4.531 36.126 4.765 ;
     RECT  30.78 4.693 33.498 4.801 ;
     RECT  0.108 3.955 0.558 4.877 ;
     RECT  2.415 3.983 12.474 4.891 ;
     RECT  13.215 4.145 21.762 4.891 ;
     RECT  2.415 4.891 21.762 4.927 ;
     RECT  2.415 4.927 21.906 4.939 ;
     RECT  22.752 4.145 29.697 4.939 ;
     RECT  30.528 4.801 33.606 4.999 ;
     RECT  34.704 4.765 36.126 5.071 ;
     RECT  2.415 4.939 29.697 5.161 ;
     RECT  30.528 4.999 33.642 5.161 ;
     RECT  37.515 2.413 37.797 5.197 ;
     RECT  37.476 5.197 38.214 5.233 ;
     RECT  0.108 4.877 0.342 5.261 ;
     RECT  34.704 5.071 36.342 5.269 ;
     RECT  37.476 5.233 38.322 5.269 ;
     RECT  40.215 2.413 40.497 5.269 ;
     RECT  2.415 5.161 33.642 5.297 ;
     RECT  37.476 5.269 38.43 5.305 ;
     RECT  39.528 5.269 40.497 5.305 ;
     RECT  2.415 5.297 29.754 5.323 ;
     RECT  30.528 5.297 33.642 5.341 ;
     RECT  30.528 5.341 33.714 5.369 ;
     RECT  2.304 5.323 29.754 5.495 ;
     RECT  34.704 5.269 36.414 5.503 ;
     RECT  63.54 3.685 63.594 5.515 ;
     RECT  37.476 5.305 40.497 5.539 ;
     RECT  2.304 5.495 29.697 5.603 ;
     RECT  37.44 5.539 40.497 5.639 ;
     RECT  30.564 5.369 33.714 5.687 ;
     RECT  34.704 5.503 36.486 5.687 ;
     RECT  40.215 5.639 40.497 5.737 ;
     RECT  0.108 5.261 0.198 5.741 ;
     RECT  30.564 5.687 36.486 5.881 ;
     RECT  56.415 2.413 56.697 5.881 ;
     RECT  30.564 5.881 36.702 5.971 ;
     RECT  37.44 5.639 38.97 5.971 ;
     RECT  2.304 5.603 16.938 6.043 ;
     RECT  0.144 5.741 0.198 6.079 ;
     RECT  30.564 5.971 38.97 6.115 ;
     RECT  30.528 6.115 38.97 6.269 ;
     RECT  17.82 5.603 29.697 6.283 ;
     RECT  30.528 6.269 33.57 6.283 ;
     RECT  2.268 6.043 16.938 6.317 ;
     RECT  60.336 4.531 62.766 6.331 ;
     RECT  63.54 5.515 64.026 6.331 ;
     RECT  2.304 6.317 16.938 6.349 ;
     RECT  17.82 6.283 33.57 6.349 ;
     RECT  0.144 6.079 0.558 6.413 ;
     RECT  34.308 6.269 38.97 6.421 ;
     RECT  40.215 5.737 41.058 6.421 ;
     RECT  34.308 6.421 41.058 6.539 ;
     RECT  60.336 6.331 64.026 6.583 ;
     RECT  34.308 6.539 40.986 6.611 ;
     RECT  2.304 6.349 33.57 6.683 ;
     RECT  0.144 6.413 0.198 6.781 ;
     RECT  60.336 6.583 64.062 6.817 ;
     RECT  2.304 6.683 33.534 6.845 ;
     RECT  60.336 6.817 64.746 6.881 ;
     RECT  0.108 6.781 0.198 6.893 ;
     RECT  2.304 6.845 29.754 7.079 ;
     RECT  0.18 6.893 0.198 7.085 ;
     RECT  34.308 6.611 40.914 7.115 ;
     RECT  40.215 7.115 40.914 7.151 ;
     RECT  60.336 6.881 64.638 7.349 ;
     RECT  30.528 6.845 33.534 7.465 ;
     RECT  34.308 7.115 39.042 7.465 ;
     RECT  40.215 7.151 40.554 7.619 ;
     RECT  26.715 7.079 29.754 7.735 ;
     RECT  30.528 7.465 39.042 7.735 ;
     RECT  60.336 7.349 60.462 7.757 ;
     RECT  61.488 7.349 64.638 7.757 ;
     RECT  26.715 7.735 39.042 7.861 ;
     RECT  0.324 7.819 0.342 7.949 ;
     RECT  61.488 7.757 63.882 7.949 ;
     RECT  41.832 7.735 41.85 7.969 ;
     RECT  42.915 2.413 43.197 7.969 ;
     RECT  2.304 7.079 25.794 8.005 ;
     RECT  26.676 7.861 39.042 8.005 ;
     RECT  40.215 7.619 40.497 8.005 ;
     RECT  56.415 5.881 57.042 8.237 ;
     RECT  2.304 8.005 39.042 8.275 ;
     RECT  39.924 8.005 40.497 8.275 ;
     RECT  61.488 7.949 63.558 8.429 ;
     RECT  2.304 8.275 40.497 8.525 ;
     RECT  64.62 7.757 64.638 8.536 ;
     RECT  61.488 8.429 62.19 8.573 ;
     RECT  60.444 7.757 60.462 8.581 ;
     RECT  60.444 8.581 60.606 8.699 ;
     RECT  63.288 8.429 63.558 8.717 ;
     RECT  41.832 7.969 43.197 8.843 ;
     RECT  63.324 8.717 63.558 8.851 ;
     RECT  0.144 8.587 0.162 8.875 ;
     RECT  0.144 8.875 0.234 8.968 ;
     RECT  0.108 8.968 0.234 8.977 ;
     RECT  0.108 8.977 0.342 9.005 ;
     RECT  64.62 8.536 64.746 9.005 ;
     RECT  2.304 8.525 22.806 9.163 ;
     RECT  63.324 8.851 63.882 9.197 ;
     RECT  2.268 9.163 22.806 9.239 ;
     RECT  64.656 9.005 64.746 9.275 ;
     RECT  64.656 9.275 64.674 9.293 ;
     RECT  63.828 9.197 63.882 9.319 ;
     RECT  2.304 9.239 22.806 9.355 ;
     RECT  23.58 8.525 40.497 9.355 ;
     RECT  2.304 9.355 40.497 9.509 ;
     RECT  41.832 8.843 41.85 9.581 ;
     RECT  46.764 9.211 46.782 9.677 ;
     RECT  54.72 9.211 54.738 9.677 ;
     RECT  2.304 9.509 35.514 9.779 ;
     RECT  60.588 8.699 60.606 9.823 ;
     RECT  0.324 9.005 0.342 9.869 ;
     RECT  45.615 2.413 45.897 9.895 ;
     RECT  63.828 9.319 63.918 9.923 ;
     RECT  63.864 9.923 63.918 9.931 ;
     RECT  42.66 8.843 43.197 9.959 ;
     RECT  61.815 8.573 62.19 9.965 ;
     RECT  2.304 9.779 35.334 10.085 ;
     RECT  0.36 10.027 0.378 10.157 ;
     RECT  45.615 9.895 46.422 10.229 ;
     RECT  1.152 9.499 1.17 10.253 ;
     RECT  36.252 9.509 40.497 10.291 ;
     RECT  2.304 10.085 3.546 10.427 ;
     RECT  63.864 9.931 63.954 10.541 ;
     RECT  36.18 10.291 40.497 10.597 ;
     RECT  4.284 10.085 35.334 10.733 ;
     RECT  36.108 10.597 40.497 10.733 ;
     RECT  4.284 10.733 6.93 10.781 ;
     RECT  41.508 10.597 41.526 10.859 ;
     RECT  36.108 10.733 39.006 10.867 ;
     RECT  7.776 10.733 35.334 10.891 ;
     RECT  36.072 10.867 39.006 10.891 ;
     RECT  61.815 9.965 62.097 10.891 ;
     RECT  62.82 10.603 62.838 10.891 ;
     RECT  60.444 9.823 61.002 10.975 ;
     RECT  61.815 10.891 62.838 10.975 ;
     RECT  2.376 10.427 3.546 11.011 ;
     RECT  4.284 10.781 6.786 11.011 ;
     RECT  2.376 11.011 6.786 11.129 ;
     RECT  60.444 10.975 62.838 11.165 ;
     RECT  42.915 9.959 43.197 11.407 ;
     RECT  59.115 3.713 59.397 11.407 ;
     RECT  63.864 10.541 63.918 11.479 ;
     RECT  58.716 11.407 59.397 11.507 ;
     RECT  7.776 10.891 39.006 11.515 ;
     RECT  63.864 11.479 63.954 11.597 ;
     RECT  61.815 11.165 62.838 11.659 ;
     RECT  63.864 11.597 63.918 11.659 ;
     RECT  7.704 11.515 39.006 11.741 ;
     RECT  2.415 11.129 6.786 11.785 ;
     RECT  33.336 11.741 39.006 11.821 ;
     RECT  64.728 11.803 64.746 11.821 ;
     RECT  46.764 11.707 46.782 11.837 ;
     RECT  54.72 11.707 54.738 11.837 ;
     RECT  64.656 11.821 64.746 11.849 ;
     RECT  64.656 11.849 64.674 11.885 ;
     RECT  7.704 11.741 32.49 11.933 ;
     RECT  7.815 11.933 32.49 11.939 ;
     RECT  7.815 11.939 29.934 11.975 ;
     RECT  33.336 11.821 39.366 12.047 ;
     RECT  60.444 11.165 60.966 12.083 ;
     RECT  60.48 12.083 60.966 12.091 ;
     RECT  61.815 11.659 63.918 12.091 ;
     RECT  7.815 11.975 29.697 12.209 ;
     RECT  30.78 11.939 32.49 12.209 ;
     RECT  42.768 11.407 43.197 12.217 ;
     RECT  42.732 12.217 43.197 12.317 ;
     RECT  33.552 12.047 39.366 12.451 ;
     RECT  40.215 10.733 40.497 12.451 ;
     RECT  13.104 12.209 29.697 12.479 ;
     RECT  30.816 12.209 32.49 12.479 ;
     RECT  31.356 12.479 32.49 12.515 ;
     RECT  59.115 11.507 59.397 12.757 ;
     RECT  60.48 12.091 63.918 12.811 ;
     RECT  21.096 12.479 29.697 12.857 ;
     RECT  60.48 12.811 63.954 12.857 ;
     RECT  7.815 12.209 12.366 12.865 ;
     RECT  33.552 12.451 40.497 12.893 ;
     RECT  33.552 12.893 38.97 12.901 ;
     RECT  58.716 12.757 59.397 12.929 ;
     RECT  60.516 12.857 63.918 12.929 ;
     RECT  2.415 11.785 6.894 13.051 ;
     RECT  28.044 12.857 29.697 13.055 ;
     RECT  33.3 12.901 38.97 13.055 ;
     RECT  39.708 12.893 40.497 13.055 ;
     RECT  60.516 12.929 63.882 13.055 ;
     RECT  28.44 13.055 29.697 13.091 ;
     RECT  40.104 13.055 40.497 13.091 ;
     RECT  60.984 13.055 63.882 13.091 ;
     RECT  7.704 12.865 12.366 13.099 ;
     RECT  13.104 12.479 20.106 13.099 ;
     RECT  60.984 13.091 63.342 13.127 ;
     RECT  7.704 13.099 20.106 13.261 ;
     RECT  21.096 12.857 26.997 13.261 ;
     RECT  28.62 13.091 29.697 13.289 ;
     RECT  38.52 13.055 38.754 13.289 ;
     RECT  7.704 13.261 26.997 13.331 ;
     RECT  2.415 13.051 6.93 13.333 ;
     RECT  7.704 13.331 21.762 13.333 ;
     RECT  60.984 13.127 63.306 13.433 ;
     RECT  60.984 13.433 62.097 13.469 ;
     RECT  22.572 13.331 26.997 13.627 ;
     RECT  22.572 13.627 27.09 13.667 ;
     RECT  63.288 13.433 63.306 13.703 ;
     RECT  2.415 13.333 21.762 13.709 ;
     RECT  31.392 12.515 32.397 13.945 ;
     RECT  33.588 13.055 37.797 13.945 ;
     RECT  60.984 13.469 61.074 14.009 ;
     RECT  38.52 13.289 38.718 14.099 ;
     RECT  31.392 13.945 37.797 14.135 ;
     RECT  31.392 14.135 35.097 14.171 ;
     RECT  35.82 14.135 37.797 14.171 ;
     RECT  22.608 13.667 27.09 14.203 ;
     RECT  2.415 13.709 16.794 14.237 ;
     RECT  35.892 14.171 37.797 14.243 ;
     RECT  22.608 14.203 27.486 14.251 ;
     RECT  28.692 13.289 29.697 14.251 ;
     RECT  2.415 14.237 6.21 14.279 ;
     RECT  61.056 14.009 61.074 14.279 ;
     RECT  22.608 14.251 29.697 14.719 ;
     RECT  61.815 13.469 62.097 14.791 ;
     RECT  31.392 14.171 33.174 14.953 ;
     RECT  33.912 14.171 35.097 14.953 ;
     RECT  7.2 14.237 16.794 15.019 ;
     RECT  17.532 13.709 21.762 15.019 ;
     RECT  7.2 15.019 21.762 15.053 ;
     RECT  22.608 14.719 29.898 15.061 ;
     RECT  36.18 14.243 37.797 15.061 ;
     RECT  38.52 14.099 38.538 15.061 ;
     RECT  61.236 14.791 62.097 15.061 ;
     RECT  22.608 15.061 30.006 15.187 ;
     RECT  7.2 15.053 12.294 15.259 ;
     RECT  31.392 14.953 35.097 15.295 ;
     RECT  60.588 15.061 62.097 15.295 ;
     RECT  22.608 15.187 30.15 15.307 ;
     RECT  31.392 15.295 35.37 15.331 ;
     RECT  36.18 15.061 38.538 15.331 ;
     RECT  22.608 15.307 30.366 15.565 ;
     RECT  31.392 15.331 38.538 15.565 ;
     RECT  2.415 14.279 6.138 15.835 ;
     RECT  6.912 15.259 12.294 15.835 ;
     RECT  13.104 15.053 21.762 15.835 ;
     RECT  22.608 15.565 38.538 15.835 ;
     RECT  60.444 15.295 62.097 15.989 ;
     RECT  2.415 15.835 12.294 15.997 ;
     RECT  2.415 15.997 12.366 16.027 ;
     RECT  13.104 15.835 38.538 16.027 ;
     RECT  2.415 16.027 38.538 16.141 ;
     RECT  2.415 16.141 38.646 16.405 ;
     RECT  63.576 15.961 63.594 16.411 ;
     RECT  2.415 16.405 38.862 16.445 ;
     RECT  2.415 16.445 38.646 16.529 ;
     RECT  60.588 15.989 62.097 16.795 ;
     RECT  60.12 16.795 62.097 16.807 ;
     RECT  62.964 16.411 63.594 16.807 ;
     RECT  2.415 16.529 38.574 16.871 ;
     RECT  0.144 16.951 0.162 17.041 ;
     RECT  2.415 16.871 17.19 17.105 ;
     RECT  56.415 8.237 56.697 17.221 ;
     RECT  0.108 17.041 0.162 17.261 ;
     RECT  2.415 17.105 14.058 17.311 ;
     RECT  18.108 16.871 38.574 17.455 ;
     RECT  60.12 16.807 63.594 17.581 ;
     RECT  0.144 17.261 0.162 17.653 ;
     RECT  18.108 17.455 38.61 17.689 ;
     RECT  18.108 17.689 38.682 17.707 ;
     RECT  14.832 17.105 17.19 17.725 ;
     RECT  18.108 17.707 38.718 17.725 ;
     RECT  60.12 17.581 63.63 17.725 ;
     RECT  14.832 17.725 38.718 17.851 ;
     RECT  2.304 17.311 14.058 17.887 ;
     RECT  14.832 17.851 38.79 17.887 ;
     RECT  0.144 17.653 0.558 17.995 ;
     RECT  40.215 13.091 40.497 18.157 ;
     RECT  0.144 17.995 0.666 18.235 ;
     RECT  0.144 18.235 0.738 18.293 ;
     RECT  0.144 18.293 0.666 18.317 ;
     RECT  2.304 17.887 38.79 18.391 ;
     RECT  40.215 18.157 40.734 18.391 ;
     RECT  0.144 18.317 0.558 18.413 ;
     RECT  40.176 18.391 40.734 18.535 ;
     RECT  0.144 18.413 0.198 18.604 ;
     RECT  39.96 18.535 40.734 18.805 ;
     RECT  64.728 16.603 64.746 18.805 ;
     RECT  64.656 18.805 64.746 18.833 ;
     RECT  2.304 18.391 38.826 18.841 ;
     RECT  39.96 18.805 40.95 18.841 ;
     RECT  0.108 18.604 0.198 18.845 ;
     RECT  0.108 18.845 0.126 18.893 ;
     RECT  2.304 18.841 41.13 19.111 ;
     RECT  2.304 19.111 41.274 19.372 ;
     RECT  42.915 12.317 43.197 19.381 ;
     RECT  2.304 19.372 41.31 19.471 ;
     RECT  42.915 19.381 43.398 19.471 ;
     RECT  2.304 19.471 43.398 19.499 ;
     RECT  6.552 19.499 43.398 19.805 ;
     RECT  60.12 17.725 63.666 19.885 ;
     RECT  6.84 19.805 43.398 19.949 ;
     RECT  0.324 19.627 0.342 20.011 ;
     RECT  2.304 19.499 5.814 20.039 ;
     RECT  6.84 19.949 12.15 20.075 ;
     RECT  0.144 20.011 0.342 20.189 ;
     RECT  12.996 19.949 43.398 20.317 ;
     RECT  12.996 20.317 43.614 20.347 ;
     RECT  60.12 19.885 63.882 20.389 ;
     RECT  64.656 18.833 64.674 20.389 ;
     RECT  12.996 20.347 43.902 20.477 ;
     RECT  6.84 20.075 11.718 20.587 ;
     RECT  12.996 20.477 30.906 20.687 ;
     RECT  56.415 17.221 57.042 20.687 ;
     RECT  0.54 20.461 0.558 20.717 ;
     RECT  2.304 20.039 5.67 20.821 ;
     RECT  6.444 20.587 11.718 20.821 ;
     RECT  2.304 20.821 11.718 21.091 ;
     RECT  12.996 20.687 30.726 21.115 ;
     RECT  2.304 21.091 11.934 21.163 ;
     RECT  12.672 21.115 30.726 21.163 ;
     RECT  2.304 21.163 30.726 21.389 ;
     RECT  60.12 20.389 64.674 21.389 ;
     RECT  17.1 21.389 30.726 21.541 ;
     RECT  17.1 21.541 30.798 21.631 ;
     RECT  31.644 20.477 43.902 21.631 ;
     RECT  60.12 21.389 60.462 21.659 ;
     RECT  2.304 21.389 16.362 21.695 ;
     RECT  17.1 21.631 43.902 21.739 ;
     RECT  61.344 21.389 64.674 21.787 ;
     RECT  61.344 21.787 64.746 21.839 ;
     RECT  61.344 21.839 64.674 21.869 ;
     RECT  17.1 21.739 43.938 21.929 ;
     RECT  17.1 21.929 43.902 22.235 ;
     RECT  15.372 21.695 16.362 22.243 ;
     RECT  0.144 21.643 0.162 22.411 ;
     RECT  15.372 22.243 16.83 22.441 ;
     RECT  0.108 22.411 0.162 22.459 ;
     RECT  2.304 21.695 14.31 22.513 ;
     RECT  17.748 22.235 43.902 22.541 ;
     RECT  0.108 22.459 0.198 22.556 ;
     RECT  61.344 21.869 64.026 22.585 ;
     RECT  60.444 21.659 60.462 22.621 ;
     RECT  61.236 22.585 64.026 22.621 ;
     RECT  46.764 22.507 46.782 22.637 ;
     RECT  54.72 22.507 54.738 22.637 ;
     RECT  17.748 22.541 43.47 22.649 ;
     RECT  0.144 22.556 0.198 22.733 ;
     RECT  60.444 22.621 64.026 22.733 ;
     RECT  2.304 22.513 14.382 22.747 ;
     RECT  15.336 22.441 16.83 22.747 ;
     RECT  2.304 22.747 16.83 22.781 ;
     RECT  0.18 22.733 0.198 22.987 ;
     RECT  11.772 22.781 16.83 23.017 ;
     RECT  17.748 22.649 27.918 23.017 ;
     RECT  60.444 22.733 63.918 23.017 ;
     RECT  0.18 22.987 0.342 23.131 ;
     RECT  0.18 23.131 0.414 23.189 ;
     RECT  2.304 22.781 11.034 23.189 ;
     RECT  60.408 23.017 63.918 23.189 ;
     RECT  0.18 23.189 0.342 23.213 ;
     RECT  0.18 23.213 0.198 23.357 ;
     RECT  11.772 23.017 27.918 23.515 ;
     RECT  28.656 22.649 43.47 23.515 ;
     RECT  2.376 23.189 11.034 23.621 ;
     RECT  3.996 23.621 11.034 23.629 ;
     RECT  11.772 23.515 43.47 23.629 ;
     RECT  60.768 23.189 63.918 23.693 ;
     RECT  2.376 23.621 2.862 23.819 ;
     RECT  2.415 23.819 2.862 23.891 ;
     RECT  3.996 23.629 43.47 23.899 ;
     RECT  3.996 23.899 43.65 23.927 ;
     RECT  4.392 23.927 43.65 24.089 ;
     RECT  4.392 24.089 43.362 24.125 ;
     RECT  63.54 23.693 63.918 24.133 ;
     RECT  59.115 12.929 59.397 24.205 ;
     RECT  5.115 24.125 43.362 24.233 ;
     RECT  58.788 24.205 59.397 24.241 ;
     RECT  60.768 23.693 62.73 24.241 ;
     RECT  5.115 24.233 6.246 24.269 ;
     RECT  63.54 24.133 63.99 24.269 ;
     RECT  44.172 24.241 44.19 24.359 ;
     RECT  60.732 24.241 62.73 24.427 ;
     RECT  7.092 24.233 43.362 24.431 ;
     RECT  63.54 24.269 63.954 24.467 ;
     RECT  7.308 24.431 43.362 24.503 ;
     RECT  48.315 2.413 48.597 24.511 ;
     RECT  5.115 24.269 5.742 24.539 ;
     RECT  47.88 24.511 48.597 24.629 ;
     RECT  7.344 24.503 43.362 24.665 ;
     RECT  58.716 24.241 59.397 24.773 ;
     RECT  7.344 24.665 40.734 24.809 ;
     RECT  41.508 24.665 43.362 24.899 ;
     RECT  60.732 24.427 62.766 24.907 ;
     RECT  63.54 24.467 63.918 24.907 ;
     RECT  7.344 24.809 40.497 24.989 ;
     RECT  7.344 24.989 34.002 25.007 ;
     RECT  7.344 25.007 33.894 25.169 ;
     RECT  34.815 24.989 40.497 25.169 ;
     RECT  60.732 24.907 63.918 25.195 ;
     RECT  23.472 25.169 33.894 25.205 ;
     RECT  41.508 24.899 43.197 25.205 ;
     RECT  59.115 24.773 59.397 25.249 ;
     RECT  32.115 25.205 33.894 25.313 ;
     RECT  60.732 25.195 63.954 25.349 ;
     RECT  23.472 25.205 31.086 25.439 ;
     RECT  32.115 25.313 33.822 25.439 ;
     RECT  41.832 25.205 43.197 25.439 ;
     RECT  32.115 25.439 33.354 25.475 ;
     RECT  41.832 25.439 42.174 25.475 ;
     RECT  35.892 25.169 39.006 25.511 ;
     RECT  35.892 25.511 36.378 25.547 ;
     RECT  40.104 25.169 40.497 25.547 ;
     RECT  7.344 25.169 22.734 25.591 ;
     RECT  60.732 25.349 63.882 25.619 ;
     RECT  37.515 25.511 39.006 25.709 ;
     RECT  6.372 25.681 6.39 25.757 ;
     RECT  7.308 25.591 22.734 25.853 ;
     RECT  59.115 25.249 59.49 25.853 ;
     RECT  61.815 25.619 63.882 25.853 ;
     RECT  59.115 25.853 59.397 25.861 ;
     RECT  9.612 25.853 22.734 25.979 ;
     RECT  37.515 25.709 38.754 25.979 ;
     RECT  63.288 25.853 63.882 25.997 ;
     RECT  37.515 25.979 38.646 26.051 ;
     RECT  58.716 25.861 59.397 26.051 ;
     RECT  61.815 25.853 62.334 26.051 ;
     RECT  20.232 25.979 22.734 26.123 ;
     RECT  20.484 26.123 22.734 26.131 ;
     RECT  23.472 25.439 30.618 26.131 ;
     RECT  20.484 26.131 30.618 26.159 ;
     RECT  63.288 25.997 63.306 26.159 ;
     RECT  7.308 25.853 8.73 26.285 ;
     RECT  37.515 26.051 38.286 26.285 ;
     RECT  20.556 26.159 30.618 26.293 ;
     RECT  33.336 25.475 33.354 26.321 ;
     RECT  60.732 25.619 61.074 26.333 ;
     RECT  20.556 26.293 31.014 26.429 ;
     RECT  60.984 26.333 61.074 26.429 ;
     RECT  20.556 26.429 30.942 26.519 ;
     RECT  36 25.547 36.378 26.519 ;
     RECT  20.556 26.519 30.15 26.591 ;
     RECT  36.36 26.519 36.378 26.699 ;
     RECT  20.556 26.591 29.898 26.789 ;
     RECT  9.612 25.979 19.386 26.825 ;
     RECT  7.452 26.285 8.73 26.861 ;
     RECT  7.596 26.861 8.73 26.941 ;
     RECT  9.612 26.825 16.578 26.941 ;
     RECT  20.556 26.789 29.697 26.941 ;
     RECT  7.596 26.941 16.578 27.095 ;
     RECT  7.815 27.095 16.578 27.167 ;
     RECT  20.376 26.941 29.697 27.167 ;
     RECT  17.352 26.825 19.386 27.175 ;
     RECT  20.376 27.167 22.734 27.175 ;
     RECT  7.815 27.167 12.294 27.329 ;
     RECT  17.352 27.175 22.734 27.329 ;
     RECT  7.815 27.329 8.586 27.365 ;
     RECT  23.688 27.167 29.697 27.365 ;
     RECT  23.688 27.365 27.09 27.389 ;
     RECT  2.415 23.891 2.697 27.557 ;
     RECT  5.115 24.539 5.397 27.557 ;
     RECT  7.815 27.365 8.097 27.557 ;
     RECT  13.215 27.167 16.197 27.557 ;
     RECT  17.352 27.329 22.41 27.557 ;
     RECT  24.015 27.389 27.09 27.557 ;
     RECT  32.115 25.475 32.397 27.557 ;
     RECT  34.815 25.169 35.097 27.557 ;
     RECT  37.515 26.285 37.797 27.557 ;
     RECT  40.215 25.547 40.497 27.557 ;
     RECT  42.915 25.439 43.197 27.557 ;
     RECT  45.615 10.229 45.897 27.557 ;
     RECT  48.315 24.629 48.597 27.557 ;
     RECT  51.015 2.413 51.297 27.557 ;
     RECT  53.715 2.413 53.997 27.557 ;
     RECT  56.415 20.687 56.697 27.557 ;
     RECT  59.115 26.051 59.397 27.557 ;
     RECT  61.815 26.051 62.097 27.557 ;
     RECT  9.756 27.329 12.294 27.599 ;
     RECT  18.807 27.557 22.41 27.599 ;
     RECT  24.207 27.557 27.09 27.599 ;
     RECT  28.116 27.365 28.206 27.599 ;
     RECT  29.124 27.365 29.697 27.599 ;
     RECT  17.352 27.557 18.054 27.635 ;
     RECT  19.692 27.599 22.302 27.635 ;
     RECT  28.116 27.599 28.134 27.635 ;
     RECT  19.692 27.635 22.266 27.671 ;
     RECT  29.232 27.599 29.697 27.671 ;
     RECT  25.596 27.599 26.118 27.677 ;
     RECT  24.207 27.599 24.714 27.694 ;
     RECT  13.407 27.557 15.354 27.707 ;
     RECT  17.352 27.635 17.766 27.707 ;
     RECT  25.596 27.677 25.65 27.707 ;
     RECT  9.9 27.599 10.797 27.743 ;
     RECT  19.692 27.671 20.142 27.743 ;
     RECT  25.596 27.707 25.614 27.743 ;
     RECT  20.916 27.671 22.266 27.779 ;
     RECT  2.607 27.557 2.697 27.827 ;
     RECT  5.307 27.557 5.397 27.827 ;
     RECT  8.007 27.557 8.097 27.827 ;
     RECT  9.972 27.743 10.797 27.827 ;
     RECT  13.407 27.707 14.814 27.827 ;
     RECT  16.107 27.557 16.197 27.827 ;
     RECT  18.807 27.599 18.897 27.827 ;
     RECT  20.916 27.779 21.597 27.827 ;
     RECT  24.207 27.694 24.297 27.827 ;
     RECT  26.907 27.599 26.997 27.827 ;
     RECT  29.607 27.671 29.697 27.827 ;
     RECT  32.307 27.557 32.397 27.827 ;
     RECT  35.007 27.557 35.097 27.827 ;
     RECT  37.707 27.557 37.797 27.827 ;
     RECT  40.407 27.557 40.497 27.827 ;
     RECT  43.107 27.557 43.197 27.827 ;
     RECT  45.807 27.557 45.897 27.827 ;
     RECT  48.507 27.557 48.597 27.827 ;
     RECT  51.207 27.557 51.297 27.827 ;
     RECT  53.907 27.557 53.997 27.827 ;
     RECT  56.607 27.557 56.697 27.827 ;
     RECT  59.307 27.557 59.397 27.827 ;
     RECT  62.007 27.557 62.097 27.827 ;
     RECT  9.972 27.827 9.99 27.869 ;
     RECT  19.692 27.743 19.71 27.869 ;
     RECT  60.984 26.429 61.002 27.869 ;
     RECT  17.1 27.841 17.118 27.941 ;
     RECT  20.916 27.827 21.366 27.941 ;
     RECT  20.916 27.941 20.934 28.211 ;
     RECT  14.004 27.827 14.814 29.659 ;
     RECT  13.86 29.659 14.814 30.173 ;
     RECT  13.86 30.173 14.526 30.179 ;
     RECT  13.878 30.179 13.932 30.204 ;
     RECT  13.95 30.179 14.004 30.204 ;
     RECT  14.022 30.179 14.076 30.204 ;
     RECT  14.094 30.179 14.148 30.204 ;
     RECT  14.166 30.179 14.22 30.204 ;
     RECT  14.238 30.179 14.292 30.204 ;
     RECT  14.31 30.179 14.364 30.204 ;
     RECT  14.382 30.179 14.436 30.204 ;
     RECT  14.454 30.179 14.508 30.204 ;
    LAYER M4 ;
     RECT  0.084 17.232 0.133 17.256 ;
     RECT  0.06 17.256 0.133 17.328 ;
     RECT  0.084 17.328 0.133 17.352 ;
     RECT  0.06 17.352 0.133 17.424 ;
     RECT  0.084 17.424 0.133 17.448 ;
     RECT  0.06 17.448 0.133 17.52 ;
     RECT  0.084 17.52 0.133 17.544 ;
     RECT  0.06 17.544 0.133 17.616 ;
     RECT  0.084 17.616 0.133 17.64 ;
     RECT  0.06 17.64 0.133 17.712 ;
     RECT  0.084 17.712 0.133 17.736 ;
     RECT  0.06 17.736 0.133 17.808 ;
     RECT  0.084 17.808 0.133 17.832 ;
     RECT  0.06 17.832 0.133 17.904 ;
     RECT  0.084 17.904 0.133 17.928 ;
     RECT  0.06 17.928 0.133 18 ;
     RECT  0.084 18 0.133 18.024 ;
     RECT  0.06 18.024 0.133 18.096 ;
     RECT  0.084 18.096 0.133 18.12 ;
     RECT  0.06 18.12 0.133 18.192 ;
     RECT  0.084 18.192 0.133 18.216 ;
     RECT  0.06 18.216 0.133 18.288 ;
     RECT  0.084 18.288 0.133 18.312 ;
     RECT  0.06 18.312 0.133 18.384 ;
     RECT  0.084 18.384 0.133 18.408 ;
     RECT  0.06 18.408 0.133 18.48 ;
     RECT  0.084 18.48 0.133 18.504 ;
     RECT  0.06 18.504 0.133 18.576 ;
     RECT  0.084 18.576 0.133 18.6 ;
     RECT  0.06 18.6 0.133 18.672 ;
     RECT  0.084 18.672 0.133 18.696 ;
     RECT  0.06 18.696 0.133 18.768 ;
     RECT  0.084 18.768 0.133 18.792 ;
     RECT  0.06 18.792 0.133 18.864 ;
     RECT  0.084 18.864 0.133 18.888 ;
     RECT  0.06 18.888 0.133 18.96 ;
     RECT  0.084 18.96 0.133 18.984 ;
     RECT  0.06 18.984 0.133 19.056 ;
     RECT  0.084 19.056 0.133 19.08 ;
     RECT  0.06 19.08 0.133 19.152 ;
     RECT  0.084 19.152 0.133 19.176 ;
     RECT  0.06 19.176 0.133 19.248 ;
     RECT  0.084 19.248 0.133 19.272 ;
     RECT  0.06 19.272 0.133 19.344 ;
     RECT  0.084 19.344 0.133 19.368 ;
     RECT  0.06 19.368 0.133 19.44 ;
     RECT  0.084 19.44 0.133 19.464 ;
     RECT  0.06 19.464 0.133 19.536 ;
     RECT  0.084 19.536 0.133 19.56 ;
     RECT  0.06 19.56 0.133 19.632 ;
     RECT  0.084 19.632 0.133 19.656 ;
     RECT  0.06 19.656 0.133 19.728 ;
     RECT  0.084 19.728 0.133 19.752 ;
     RECT  0.06 19.752 0.133 19.824 ;
     RECT  0.084 19.824 0.133 19.848 ;
     RECT  0.06 19.848 0.133 19.92 ;
     RECT  0.084 19.92 0.133 19.944 ;
     RECT  0.06 19.944 0.133 20.016 ;
     RECT  0.084 20.016 0.133 20.04 ;
     RECT  0.06 20.04 0.133 20.112 ;
     RECT  0.084 20.112 0.133 20.136 ;
     RECT  0.06 20.136 0.133 20.208 ;
     RECT  0.084 20.208 0.133 20.232 ;
     RECT  0.06 20.232 0.133 20.304 ;
     RECT  0.084 20.304 0.133 20.328 ;
     RECT  0.06 20.328 0.133 20.4 ;
     RECT  0.084 20.4 0.133 20.424 ;
     RECT  0.06 20.424 0.133 20.496 ;
     RECT  0.084 20.496 0.133 20.52 ;
     RECT  0.06 20.52 0.133 20.592 ;
     RECT  0.084 20.592 0.133 20.616 ;
     RECT  0.06 20.616 0.133 20.688 ;
     RECT  0.084 20.688 0.133 20.712 ;
     RECT  0.06 20.712 0.133 20.784 ;
     RECT  0.084 20.784 0.133 20.808 ;
     RECT  0.06 20.808 0.133 20.88 ;
     RECT  0.084 20.88 0.133 20.904 ;
     RECT  0.06 20.904 0.133 20.976 ;
     RECT  0.084 20.976 0.133 21 ;
     RECT  0.06 21 0.133 21.072 ;
     RECT  0.084 21.072 0.133 21.096 ;
     RECT  0.06 21.096 0.133 21.168 ;
     RECT  0.084 21.168 0.133 21.192 ;
     RECT  0.06 21.192 0.133 21.264 ;
     RECT  0.084 21.264 0.133 21.288 ;
     RECT  0.06 21.288 0.133 21.36 ;
     RECT  0.084 21.36 0.133 21.384 ;
     RECT  0.06 21.384 0.133 21.456 ;
     RECT  0.084 21.456 0.133 21.48 ;
     RECT  0.06 21.48 0.133 21.552 ;
     RECT  0.084 21.552 0.133 21.576 ;
     RECT  0.06 21.576 0.133 21.648 ;
     RECT  0.084 21.648 0.133 21.672 ;
     RECT  0.06 21.672 0.133 21.744 ;
     RECT  0.084 21.744 0.133 21.768 ;
     RECT  0.06 21.768 0.133 21.84 ;
     RECT  0.084 21.84 0.133 21.864 ;
     RECT  0.06 21.864 0.133 21.936 ;
     RECT  0.084 21.936 0.133 21.96 ;
     RECT  0.06 21.96 0.133 22.032 ;
     RECT  0.084 22.032 0.133 22.056 ;
     RECT  0.06 22.056 0.133 22.128 ;
     RECT  0.084 22.128 0.133 22.152 ;
     RECT  0.06 22.152 0.133 22.224 ;
     RECT  0.084 22.224 0.133 22.248 ;
     RECT  0.06 22.248 0.133 22.32 ;
     RECT  0.084 22.32 0.133 22.344 ;
     RECT  0.06 22.344 0.133 22.416 ;
     RECT  0.084 22.416 0.133 22.44 ;
     RECT  0.06 22.44 0.133 22.512 ;
     RECT  0.084 22.512 0.133 22.536 ;
     RECT  0.06 22.536 0.133 22.608 ;
     RECT  0.084 22.608 0.133 22.632 ;
     RECT  0.06 22.632 0.133 22.704 ;
     RECT  0.084 22.704 0.133 22.728 ;
     RECT  0.06 22.728 0.133 22.8 ;
     RECT  0.084 22.8 0.133 22.824 ;
     RECT  0.06 22.824 0.133 22.896 ;
     RECT  0.084 22.896 0.133 22.92 ;
     RECT  0.06 22.92 0.133 22.992 ;
     RECT  0.084 22.992 0.133 23.016 ;
     RECT  0.06 23.016 0.133 23.088 ;
     RECT  0.084 23.088 0.133 23.112 ;
     RECT  0.06 23.112 0.133 23.184 ;
     RECT  0.084 23.184 0.133 23.208 ;
     RECT  0.06 23.208 0.133 23.28 ;
     RECT  0.084 23.28 0.133 23.304 ;
     RECT  0.133 17.232 0.137 23.592 ;
     RECT  0.084 4.176 0.569 4.2 ;
     RECT  0.06 4.2 0.569 4.272 ;
     RECT  0.084 4.272 0.569 4.296 ;
     RECT  0.06 4.296 0.569 4.368 ;
     RECT  0.084 4.368 0.569 4.392 ;
     RECT  0.06 4.392 0.569 4.464 ;
     RECT  0.084 4.464 0.569 4.488 ;
     RECT  0.06 4.488 0.569 4.56 ;
     RECT  0.084 4.56 0.569 4.584 ;
     RECT  0.06 4.584 0.569 4.656 ;
     RECT  0.084 4.656 0.569 4.68 ;
     RECT  0.06 4.68 0.569 4.752 ;
     RECT  0.084 4.752 0.569 4.776 ;
     RECT  0.06 4.776 0.569 4.848 ;
     RECT  0.084 4.848 0.569 4.872 ;
     RECT  0.06 4.872 0.569 4.944 ;
     RECT  0.084 4.944 0.569 4.968 ;
     RECT  0.06 4.968 0.569 5.04 ;
     RECT  0.084 5.04 0.569 5.064 ;
     RECT  0.06 5.064 0.569 5.136 ;
     RECT  0.084 5.136 0.569 5.16 ;
     RECT  0.06 5.16 0.569 5.232 ;
     RECT  0.084 5.232 0.569 5.256 ;
     RECT  0.06 5.256 0.569 5.328 ;
     RECT  0.084 5.328 0.569 5.352 ;
     RECT  0.06 5.352 0.569 5.424 ;
     RECT  0.084 5.424 0.569 5.448 ;
     RECT  0.06 5.448 0.569 5.52 ;
     RECT  0.084 5.52 0.569 5.544 ;
     RECT  0.06 5.544 0.569 5.616 ;
     RECT  0.084 5.616 0.569 5.64 ;
     RECT  0.06 5.64 0.569 5.712 ;
     RECT  0.084 5.712 0.569 5.736 ;
     RECT  0.06 5.736 0.569 5.808 ;
     RECT  0.084 5.808 0.569 5.832 ;
     RECT  0.06 5.832 0.569 5.904 ;
     RECT  0.084 5.904 0.569 5.928 ;
     RECT  0.06 5.928 0.569 6 ;
     RECT  0.084 6 0.569 6.024 ;
     RECT  0.06 6.024 0.569 6.096 ;
     RECT  0.084 6.096 0.569 6.12 ;
     RECT  0.06 6.12 0.569 6.192 ;
     RECT  0.084 6.192 0.569 6.216 ;
     RECT  0.06 6.216 0.569 6.288 ;
     RECT  0.084 6.288 0.569 6.312 ;
     RECT  0.06 6.312 0.569 6.384 ;
     RECT  0.084 6.384 0.569 6.408 ;
     RECT  0.06 6.408 0.569 6.48 ;
     RECT  0.084 6.48 0.569 6.504 ;
     RECT  0.06 6.504 0.569 6.576 ;
     RECT  0.084 6.576 0.569 6.6 ;
     RECT  0.06 6.6 0.569 6.672 ;
     RECT  0.084 6.672 0.569 6.696 ;
     RECT  0.06 6.696 0.569 6.768 ;
     RECT  0.084 6.768 0.569 6.792 ;
     RECT  0.06 6.792 0.569 6.864 ;
     RECT  0.084 6.864 0.569 6.888 ;
     RECT  0.06 6.888 0.569 6.96 ;
     RECT  0.084 6.96 0.569 6.984 ;
     RECT  0.06 6.984 0.569 7.056 ;
     RECT  0.084 7.056 0.569 7.08 ;
     RECT  0.06 7.08 0.569 7.152 ;
     RECT  0.084 7.152 0.569 7.176 ;
     RECT  0.06 7.176 0.569 7.248 ;
     RECT  0.084 7.248 0.569 7.272 ;
     RECT  0.06 7.272 0.569 7.344 ;
     RECT  0.084 7.344 0.569 7.368 ;
     RECT  0.06 7.368 0.569 7.44 ;
     RECT  0.084 7.44 0.569 7.464 ;
     RECT  0.06 7.464 0.569 7.536 ;
     RECT  0.084 7.536 0.569 7.56 ;
     RECT  0.06 7.56 0.569 7.632 ;
     RECT  0.084 7.632 0.569 7.656 ;
     RECT  0.06 7.656 0.569 7.728 ;
     RECT  0.084 7.728 0.569 7.752 ;
     RECT  0.06 7.752 0.569 7.824 ;
     RECT  0.084 7.824 0.569 7.848 ;
     RECT  0.06 7.848 0.569 7.92 ;
     RECT  0.084 7.92 0.569 7.944 ;
     RECT  0.06 7.944 0.569 8.016 ;
     RECT  0.084 8.016 0.569 8.04 ;
     RECT  0.06 8.04 0.569 8.112 ;
     RECT  0.084 8.112 0.569 8.136 ;
     RECT  0.06 8.136 0.569 8.208 ;
     RECT  0.084 8.208 0.569 8.232 ;
     RECT  0.06 8.232 0.569 8.304 ;
     RECT  0.084 8.304 0.569 8.328 ;
     RECT  0.06 8.328 0.569 8.4 ;
     RECT  0.084 8.4 0.569 8.424 ;
     RECT  0.06 8.424 0.569 8.496 ;
     RECT  0.084 8.496 0.569 8.52 ;
     RECT  0.06 8.52 0.569 8.592 ;
     RECT  0.084 8.592 0.569 8.616 ;
     RECT  0.06 8.616 0.569 8.688 ;
     RECT  0.084 8.688 0.569 8.712 ;
     RECT  0.06 8.712 0.569 8.784 ;
     RECT  0.084 8.784 0.569 8.808 ;
     RECT  0.06 8.808 0.569 8.88 ;
     RECT  0.084 8.88 0.569 8.904 ;
     RECT  0.06 8.904 0.569 8.976 ;
     RECT  0.084 8.976 0.569 9 ;
     RECT  0.06 9 0.569 9.072 ;
     RECT  0.084 9.072 0.569 9.096 ;
     RECT  0.06 9.096 0.569 9.168 ;
     RECT  0.084 9.168 0.569 9.192 ;
     RECT  0.06 9.192 0.569 9.264 ;
     RECT  0.084 9.264 0.569 9.288 ;
     RECT  0.06 9.288 0.569 9.36 ;
     RECT  0.084 9.36 0.569 9.384 ;
     RECT  0.06 9.384 0.569 9.456 ;
     RECT  0.084 9.456 0.569 9.48 ;
     RECT  0.06 9.48 0.569 9.552 ;
     RECT  0.084 9.552 0.569 9.576 ;
     RECT  0.06 9.576 0.569 9.648 ;
     RECT  0.084 9.648 0.569 9.672 ;
     RECT  0.06 9.672 0.569 9.744 ;
     RECT  0.084 9.744 0.569 9.768 ;
     RECT  0.06 9.768 0.569 9.84 ;
     RECT  0.084 9.84 0.569 9.864 ;
     RECT  0.06 9.864 0.569 9.936 ;
     RECT  0.084 9.936 0.569 9.96 ;
     RECT  0.06 9.96 0.569 10.032 ;
     RECT  0.084 10.032 0.569 10.056 ;
     RECT  0.06 10.056 0.569 10.128 ;
     RECT  0.084 10.128 0.569 10.152 ;
     RECT  0.06 10.152 0.569 10.224 ;
     RECT  0.084 10.224 0.569 10.248 ;
     RECT  0.569 4.752 1.181 10.248 ;
     RECT  1.181 4.752 2.408 10.152 ;
     RECT  0.137 17.328 2.408 23.592 ;
     RECT  2.408 2.148 2.512 27.552 ;
     RECT  2.512 2.418 2.6 27.552 ;
     RECT  2.6 2.418 2.704 27.822 ;
     RECT  2.704 3.888 2.981 11.016 ;
     RECT  2.704 13.92 3.697 13.944 ;
     RECT  2.704 12 3.949 12.024 ;
     RECT  3.949 12 3.98 12.552 ;
     RECT  3.697 13.68 3.98 13.944 ;
     RECT  2.981 3.888 4.021 9.864 ;
     RECT  2.981 10.992 4.021 11.016 ;
     RECT  2.704 16.272 4.093 16.296 ;
     RECT  2.704 17.328 4.093 23.592 ;
     RECT  4.021 3.888 4.129 11.016 ;
     RECT  3.98 12 4.129 13.944 ;
     RECT  2.704 15.264 4.525 15.288 ;
     RECT  4.093 16.272 4.525 23.592 ;
     RECT  3.877 2.736 5.065 2.76 ;
     RECT  5.065 2.304 5.108 2.76 ;
     RECT  4.129 3.888 5.108 13.944 ;
     RECT  4.525 15.264 5.108 23.592 ;
     RECT  5.108 2.148 5.212 27.552 ;
     RECT  5.212 2.304 5.3 27.552 ;
     RECT  5.3 2.304 5.404 27.822 ;
     RECT  5.404 2.304 5.869 14.232 ;
     RECT  5.869 13.584 5.933 14.232 ;
     RECT  5.869 2.304 6.041 12.312 ;
     RECT  5.404 15.264 6.077 23.592 ;
     RECT  6.041 3.792 6.293 12.312 ;
     RECT  6.077 15.264 6.473 23.352 ;
     RECT  6.293 3.888 6.689 12.312 ;
     RECT  5.933 14.208 6.901 14.232 ;
     RECT  6.901 13.056 7.148 14.232 ;
     RECT  6.473 15.264 7.148 22.248 ;
     RECT  5.404 25.728 7.333 25.752 ;
     RECT  6.473 23.328 7.441 23.352 ;
     RECT  7.333 25.488 7.477 25.752 ;
     RECT  7.477 25.056 7.549 25.752 ;
     RECT  7.549 24.912 7.58 25.752 ;
     RECT  7.148 13.056 7.657 22.248 ;
     RECT  7.441 23.328 7.657 23.88 ;
     RECT  6.041 2.304 7.808 2.328 ;
     RECT  6.689 3.888 7.808 11.928 ;
     RECT  7.657 13.056 7.808 23.88 ;
     RECT  7.58 24.912 7.808 26.28 ;
     RECT  7.808 2.148 7.912 27.552 ;
     RECT  7.912 2.418 8 27.552 ;
     RECT  8 2.418 8.104 27.822 ;
     RECT  8.104 2.832 8.633 27.24 ;
     RECT  8.633 14.88 8.819 26.232 ;
     RECT  8.819 14.88 9.997 25.848 ;
     RECT  8.633 27.216 9.997 27.24 ;
     RECT  8.633 2.832 10.033 13.704 ;
     RECT  9.997 14.88 10.033 27.24 ;
     RECT  10.033 2.832 10.508 27.24 ;
     RECT  10.508 2.148 10.612 27.552 ;
     RECT  10.612 2.418 10.7 27.552 ;
     RECT  10.7 2.418 10.804 27.822 ;
     RECT  10.804 10.08 10.829 13.656 ;
     RECT  10.829 10.32 10.865 13.416 ;
     RECT  10.804 14.64 11.189 27.432 ;
     RECT  11.189 15.216 11.413 27.432 ;
     RECT  10.865 10.992 11.977 13.416 ;
     RECT  10.804 3.408 11.987 8.76 ;
     RECT  11.987 8.544 12.017 8.76 ;
     RECT  11.413 15.216 12.053 26.856 ;
     RECT  12.053 24.336 12.125 26.856 ;
     RECT  12.017 8.736 12.157 8.76 ;
     RECT  11.977 10.272 12.157 13.704 ;
     RECT  11.987 3.408 12.161 7.416 ;
     RECT  12.157 8.736 12.337 13.704 ;
     RECT  12.053 15.216 12.337 23.112 ;
     RECT  12.161 3.408 12.625 5.88 ;
     RECT  12.625 3.12 12.913 5.88 ;
     RECT  12.337 8.736 13.057 23.112 ;
     RECT  12.913 3.024 13.165 5.88 ;
     RECT  12.161 6.912 13.165 7.416 ;
     RECT  13.057 8.448 13.165 23.112 ;
     RECT  13.165 3.024 13.208 7.416 ;
     RECT  13.165 8.448 13.208 23.16 ;
     RECT  12.125 24.336 13.208 26.328 ;
     RECT  13.208 2.148 13.312 27.552 ;
     RECT  13.312 2.418 13.4 27.552 ;
     RECT  13.4 2.418 13.504 27.822 ;
     RECT  13.504 24.48 13.601 27.336 ;
     RECT  13.504 14.112 13.619 18.744 ;
     RECT  13.504 8.4 13.637 11.544 ;
     RECT  13.601 24.48 13.667 24.504 ;
     RECT  13.619 14.112 13.673 18.552 ;
     RECT  13.673 14.112 13.709 18.456 ;
     RECT  13.504 12.576 13.781 12.936 ;
     RECT  11.749 29.664 13.889 29.688 ;
     RECT  13.637 8.4 13.997 9.336 ;
     RECT  13.504 19.776 14.213 23.16 ;
     RECT  13.921 30.048 14.677 30.072 ;
     RECT  14.677 30.048 14.717 30.168 ;
     RECT  13.504 3.024 14.785 7.416 ;
     RECT  13.997 8.4 14.785 9 ;
     RECT  13.601 25.536 14.785 27.336 ;
     RECT  13.637 10.368 14.861 11.544 ;
     RECT  14.785 24.624 14.861 27.336 ;
     RECT  14.861 24.624 15.145 27.192 ;
     RECT  13.781 12.576 15.181 12.792 ;
     RECT  14.213 19.776 15.217 23.112 ;
     RECT  15.145 24.192 15.217 27.192 ;
     RECT  14.785 3.024 15.397 9 ;
     RECT  13.709 15.216 15.397 18.456 ;
     RECT  15.397 15.216 15.541 18.504 ;
     RECT  15.541 15.216 15.901 18.744 ;
     RECT  15.217 19.776 15.901 27.192 ;
     RECT  15.397 2.88 15.908 9 ;
     RECT  14.861 10.464 15.908 11.544 ;
     RECT  15.181 12.576 15.908 12.888 ;
     RECT  13.709 14.112 15.908 14.136 ;
     RECT  15.901 15.216 15.908 27.192 ;
     RECT  15.908 2.148 16.012 27.552 ;
     RECT  16.012 2.418 16.1 27.552 ;
     RECT  16.1 2.418 16.204 27.822 ;
     RECT  16.204 8.544 16.337 18.744 ;
     RECT  16.337 8.544 16.373 18.552 ;
     RECT  16.204 2.736 16.589 3.048 ;
     RECT  16.373 15.024 16.589 18.552 ;
     RECT  16.373 8.544 16.595 13.704 ;
     RECT  16.589 16.32 17.485 18.552 ;
     RECT  16.204 19.776 17.485 27.192 ;
     RECT  16.589 15.024 17.557 15.288 ;
     RECT  17.485 16.32 17.557 27.192 ;
     RECT  16.589 2.736 17.612 2.76 ;
     RECT  17.612 2.736 17.653 2.904 ;
     RECT  16.204 4.176 17.653 7.224 ;
     RECT  16.595 8.544 17.701 9.864 ;
     RECT  17.701 8.448 17.917 9.864 ;
     RECT  16.595 10.944 17.917 13.704 ;
     RECT  17.917 8.448 17.953 13.704 ;
     RECT  17.557 15.024 17.953 27.192 ;
     RECT  17.653 2.736 18.608 7.224 ;
     RECT  17.953 8.448 18.608 27.192 ;
     RECT  18.608 2.148 18.712 27.552 ;
     RECT  18.712 2.304 18.8 27.552 ;
     RECT  18.8 2.304 18.904 27.822 ;
     RECT  18.904 9.792 19.433 13.128 ;
     RECT  18.904 2.304 19.649 7.416 ;
     RECT  14.717 30.144 19.667 30.168 ;
     RECT  19.649 2.64 20.003 7.416 ;
     RECT  18.904 14.448 20.009 27.192 ;
     RECT  20.009 14.64 20.045 27.192 ;
     RECT  20.003 2.64 20.147 6.12 ;
     RECT  20.003 7.2 20.473 7.416 ;
     RECT  18.904 8.4 20.473 8.568 ;
     RECT  20.473 7.2 20.509 8.568 ;
     RECT  19.433 9.792 20.509 12.6 ;
     RECT  20.147 3.12 21.301 6.12 ;
     RECT  21.301 2.784 21.308 6.12 ;
     RECT  20.509 7.2 21.308 12.6 ;
     RECT  20.045 15.024 21.308 27.192 ;
     RECT  21.308 2.148 21.412 27.552 ;
     RECT  21.412 2.418 21.5 27.552 ;
     RECT  21.5 2.418 21.604 27.822 ;
     RECT  21.604 2.784 21.701 13.32 ;
     RECT  21.604 15.024 21.701 26.328 ;
     RECT  21.701 25.104 21.917 26.328 ;
     RECT  21.917 25.104 21.953 25.128 ;
     RECT  21.701 3.12 22.349 13.32 ;
     RECT  22.349 3.12 22.421 13.08 ;
     RECT  22.421 3.12 22.457 11.496 ;
     RECT  21.701 15.216 22.565 23.976 ;
     RECT  22.457 3.312 22.637 11.496 ;
     RECT  22.565 16.512 22.957 23.976 ;
     RECT  21.917 26.256 22.993 26.328 ;
     RECT  22.421 12.576 23.033 13.08 ;
     RECT  22.705 14.208 23.093 14.232 ;
     RECT  22.565 15.216 23.093 15.384 ;
     RECT  22.957 16.512 23.569 24.696 ;
     RECT  22.637 3.312 23.605 8.568 ;
     RECT  23.569 16.512 23.677 24.936 ;
     RECT  22.993 26.256 23.677 26.376 ;
     RECT  22.637 10.128 23.857 11.496 ;
     RECT  23.605 2.832 24.008 8.568 ;
     RECT  23.857 9.84 24.008 11.496 ;
     RECT  23.033 12.576 24.008 12.888 ;
     RECT  23.093 14.208 24.008 15.384 ;
     RECT  23.677 16.512 24.008 26.376 ;
     RECT  23.677 27.36 24.008 27.384 ;
     RECT  24.008 2.148 24.112 27.552 ;
     RECT  24.112 2.418 24.2 27.552 ;
     RECT  24.2 2.418 24.304 27.822 ;
     RECT  24.304 2.832 24.515 13.08 ;
     RECT  24.304 14.208 24.545 27.672 ;
     RECT  24.545 14.784 24.725 27.672 ;
     RECT  24.725 14.784 25.481 26.568 ;
     RECT  25.481 14.784 25.657 26.328 ;
     RECT  24.515 3.024 25.945 13.08 ;
     RECT  25.945 3.024 26.341 13.416 ;
     RECT  26.341 2.832 26.708 13.416 ;
     RECT  25.657 14.4 26.708 26.328 ;
     RECT  24.725 27.648 26.708 27.672 ;
     RECT  26.708 2.148 26.812 27.672 ;
     RECT  26.812 2.418 26.9 27.672 ;
     RECT  26.9 2.418 27.004 27.822 ;
     RECT  27.004 13.632 27.299 27.336 ;
     RECT  27.299 14.208 27.497 27.336 ;
     RECT  27.004 4.224 27.749 12.6 ;
     RECT  27.004 2.832 27.929 2.856 ;
     RECT  27.749 4.512 29.408 12.6 ;
     RECT  27.497 14.4 29.408 27.336 ;
     RECT  29.408 2.148 29.512 27.552 ;
     RECT  29.512 2.418 29.6 27.552 ;
     RECT  29.6 2.418 29.704 27.822 ;
     RECT  29.704 15.264 29.873 26.328 ;
     RECT  29.873 15.312 30.305 26.328 ;
     RECT  30.305 15.312 30.377 25.32 ;
     RECT  30.377 15.36 30.413 25.32 ;
     RECT  29.704 4.512 30.805 7.224 ;
     RECT  29.704 8.496 31.237 12.6 ;
     RECT  30.805 4.416 31.489 7.224 ;
     RECT  31.237 8.208 31.489 12.6 ;
     RECT  31.489 4.416 31.597 12.6 ;
     RECT  30.413 15.36 31.705 15.768 ;
     RECT  30.413 16.8 31.705 25.128 ;
     RECT  31.705 15.36 31.877 25.128 ;
     RECT  31.597 4.416 31.909 12.984 ;
     RECT  31.909 4.416 32.108 13.08 ;
     RECT  31.877 14.832 32.108 25.128 ;
     RECT  30.305 26.304 32.108 26.328 ;
     RECT  32.108 2.148 32.212 27.552 ;
     RECT  32.212 2.418 32.3 27.552 ;
     RECT  32.3 2.418 32.404 27.822 ;
     RECT  32.404 4.416 32.789 13.992 ;
     RECT  32.404 15.312 33.113 25.128 ;
     RECT  33.113 15.456 33.203 25.128 ;
     RECT  33.203 15.456 33.509 25.032 ;
     RECT  33.509 16.608 33.545 25.032 ;
     RECT  33.545 16.608 33.587 23.544 ;
     RECT  32.789 5.52 33.689 13.992 ;
     RECT  33.587 16.608 33.725 23.448 ;
     RECT  32.789 4.416 34.405 4.44 ;
     RECT  34.405 4.416 34.808 4.536 ;
     RECT  33.689 5.52 34.808 13.8 ;
     RECT  33.509 15.456 34.808 15.48 ;
     RECT  33.725 16.608 34.808 23.4 ;
     RECT  33.545 24.528 34.808 25.032 ;
     RECT  32.404 26.304 34.808 26.328 ;
     RECT  34.808 2.148 34.912 27.552 ;
     RECT  34.912 2.418 35 27.552 ;
     RECT  35 2.418 35.104 27.822 ;
     RECT  35.104 15.36 35.201 25.032 ;
     RECT  35.201 15.36 35.267 15.48 ;
     RECT  35.201 16.56 35.891 25.032 ;
     RECT  35.891 16.608 36.065 25.032 ;
     RECT  36.065 18.816 36.101 25.032 ;
     RECT  36.101 19.296 36.133 25.032 ;
     RECT  36.133 19.296 36.281 25.08 ;
     RECT  35.104 5.52 36.467 13.8 ;
     RECT  36.467 5.52 36.533 13.704 ;
     RECT  35.104 4.512 37.508 4.536 ;
     RECT  36.533 5.52 37.508 12.888 ;
     RECT  35.267 15.36 37.508 15.384 ;
     RECT  36.065 16.608 37.508 17.784 ;
     RECT  36.281 19.296 37.508 25.032 ;
     RECT  35.104 26.304 37.508 26.328 ;
     RECT  37.508 2.148 37.612 27.552 ;
     RECT  37.612 2.418 37.7 27.552 ;
     RECT  37.7 2.418 37.804 27.822 ;
     RECT  37.804 16.416 38.051 26.328 ;
     RECT  37.804 4.512 38.62 12.888 ;
     RECT  38.051 18.72 38.693 26.328 ;
     RECT  38.051 16.416 38.729 17.736 ;
     RECT  38.693 18.72 38.765 25.032 ;
     RECT  38.729 16.416 38.873 17.496 ;
     RECT  38.62 5.52 38.945 12.888 ;
     RECT  38.945 11.472 39.017 12.888 ;
     RECT  39.017 11.712 39.161 12.888 ;
     RECT  38.62 4.512 40.208 4.536 ;
     RECT  38.945 5.52 40.208 10.152 ;
     RECT  39.161 11.712 40.208 12.84 ;
     RECT  38.873 16.608 40.208 17.496 ;
     RECT  38.765 18.816 40.208 25.032 ;
     RECT  38.693 26.304 40.208 26.328 ;
     RECT  40.208 2.148 40.312 27.552 ;
     RECT  40.312 2.418 40.4 27.552 ;
     RECT  40.4 2.418 40.504 27.822 ;
     RECT  40.504 18.816 40.643 25.032 ;
     RECT  40.643 19.296 41.569 25.032 ;
     RECT  40.504 4.512 42.908 4.536 ;
     RECT  40.504 5.52 42.908 10.152 ;
     RECT  40.504 11.712 42.908 12.6 ;
     RECT  40.504 16.608 42.908 17.496 ;
     RECT  41.569 19.296 42.908 25.08 ;
     RECT  40.504 26.304 42.908 26.328 ;
     RECT  42.908 2.148 43.012 27.552 ;
     RECT  43.012 2.418 43.1 27.552 ;
     RECT  43.1 2.418 43.204 27.822 ;
     RECT  43.204 20.352 43.913 25.032 ;
     RECT  43.204 4.512 45.608 4.536 ;
     RECT  43.204 5.52 45.608 10.152 ;
     RECT  43.204 11.712 45.608 12.6 ;
     RECT  43.204 16.608 45.608 17.496 ;
     RECT  43.204 19.296 45.608 19.32 ;
     RECT  43.913 21.12 45.608 25.032 ;
     RECT  43.204 26.304 45.608 26.328 ;
     RECT  45.608 2.148 45.712 27.552 ;
     RECT  45.712 2.418 45.8 27.552 ;
     RECT  45.8 2.418 45.904 27.822 ;
     RECT  45.904 4.512 48.308 4.536 ;
     RECT  45.904 5.52 48.308 10.152 ;
     RECT  45.904 11.712 48.308 12.6 ;
     RECT  45.904 16.608 48.308 17.496 ;
     RECT  45.904 19.296 48.308 19.32 ;
     RECT  45.904 21.12 48.308 25.032 ;
     RECT  45.904 26.304 48.308 26.328 ;
     RECT  48.308 2.148 48.412 27.552 ;
     RECT  48.412 2.418 48.5 27.552 ;
     RECT  48.5 2.418 48.604 27.822 ;
     RECT  48.604 4.512 51.008 4.536 ;
     RECT  48.604 5.52 51.008 10.152 ;
     RECT  48.604 11.712 51.008 12.6 ;
     RECT  48.604 16.608 51.008 17.496 ;
     RECT  48.604 19.296 51.008 19.32 ;
     RECT  48.604 21.12 51.008 25.032 ;
     RECT  48.604 26.304 51.008 26.328 ;
     RECT  51.008 2.148 51.112 27.552 ;
     RECT  51.112 2.418 51.2 27.552 ;
     RECT  51.2 2.418 51.304 27.822 ;
     RECT  51.304 4.512 53.708 4.536 ;
     RECT  51.304 5.52 53.708 10.152 ;
     RECT  51.304 11.712 53.708 12.6 ;
     RECT  51.304 16.608 53.708 17.496 ;
     RECT  51.304 19.296 53.708 19.32 ;
     RECT  51.304 21.12 53.708 25.032 ;
     RECT  51.304 26.304 53.708 26.328 ;
     RECT  53.708 2.148 53.812 27.552 ;
     RECT  53.812 2.418 53.9 27.552 ;
     RECT  53.9 2.418 54.004 27.822 ;
     RECT  54.004 4.512 56.408 4.536 ;
     RECT  54.004 5.52 56.408 10.152 ;
     RECT  54.004 11.712 56.408 12.6 ;
     RECT  54.004 16.608 56.408 17.496 ;
     RECT  54.004 19.296 56.408 19.32 ;
     RECT  54.004 21.12 56.408 25.032 ;
     RECT  54.004 26.304 56.408 26.328 ;
     RECT  56.408 2.148 56.512 27.552 ;
     RECT  56.512 2.418 56.6 27.552 ;
     RECT  56.6 2.418 56.704 27.822 ;
     RECT  56.704 4.512 59.108 4.536 ;
     RECT  56.704 5.52 59.108 10.152 ;
     RECT  56.704 11.712 59.108 12.6 ;
     RECT  56.704 16.608 59.108 17.496 ;
     RECT  56.704 19.296 59.108 19.32 ;
     RECT  56.704 21.12 59.108 25.032 ;
     RECT  56.704 26.304 59.108 26.328 ;
     RECT  59.108 2.148 59.212 27.552 ;
     RECT  59.212 2.418 59.3 27.552 ;
     RECT  59.3 2.418 59.404 27.822 ;
     RECT  59.404 5.52 60.433 10.152 ;
     RECT  60.433 5.52 60.577 10.728 ;
     RECT  59.404 11.712 60.577 12.6 ;
     RECT  59.404 26.304 60.761 26.328 ;
     RECT  59.404 4.512 61.808 4.536 ;
     RECT  60.577 5.52 61.808 12.6 ;
     RECT  59.404 16.608 61.808 17.496 ;
     RECT  59.404 19.296 61.808 19.32 ;
     RECT  59.404 21.12 61.808 25.032 ;
     RECT  61.808 2.148 61.912 27.552 ;
     RECT  61.912 2.418 62 27.552 ;
     RECT  62 2.418 62.104 27.822 ;
     RECT  62.104 19.296 63.313 25.704 ;
     RECT  63.313 19.296 63.349 25.8 ;
     RECT  62.104 5.52 63.353 12.936 ;
     RECT  63.349 19.296 63.461 25.896 ;
     RECT  63.461 19.92 63.853 25.896 ;
     RECT  63.353 5.52 64.037 5.544 ;
     RECT  63.353 6.864 64.692 6.888 ;
     RECT  63.353 6.888 64.716 6.96 ;
     RECT  63.353 6.96 64.692 6.984 ;
     RECT  63.353 6.984 64.716 7.056 ;
     RECT  63.353 7.056 64.692 7.08 ;
     RECT  63.353 7.08 64.716 7.152 ;
     RECT  63.353 7.152 64.692 7.176 ;
     RECT  63.353 7.176 64.716 7.248 ;
     RECT  63.353 7.248 64.692 7.272 ;
     RECT  63.353 7.272 64.716 7.344 ;
     RECT  63.353 7.344 64.692 7.368 ;
     RECT  63.353 7.368 64.716 7.44 ;
     RECT  63.353 7.44 64.692 7.464 ;
     RECT  63.353 7.464 64.716 7.536 ;
     RECT  63.353 7.536 64.692 7.56 ;
     RECT  63.353 7.56 64.716 7.632 ;
     RECT  63.353 7.632 64.692 7.656 ;
     RECT  63.353 7.656 64.716 7.728 ;
     RECT  63.353 7.728 64.692 7.752 ;
     RECT  63.353 7.752 64.716 7.824 ;
     RECT  63.353 7.824 64.692 7.848 ;
     RECT  63.353 7.848 64.716 7.92 ;
     RECT  63.353 7.92 64.692 7.944 ;
     RECT  63.353 7.944 64.716 8.016 ;
     RECT  63.353 8.016 64.692 8.04 ;
     RECT  63.353 8.04 64.716 8.112 ;
     RECT  63.353 8.112 64.692 8.136 ;
     RECT  63.353 8.136 64.716 8.208 ;
     RECT  63.353 8.208 64.692 8.232 ;
     RECT  63.353 8.232 64.716 8.304 ;
     RECT  63.353 8.304 64.692 8.328 ;
     RECT  63.353 8.328 64.716 8.4 ;
     RECT  63.353 8.4 64.692 8.424 ;
     RECT  63.353 8.424 64.716 8.496 ;
     RECT  63.353 8.496 64.692 8.52 ;
     RECT  63.353 8.52 64.716 8.592 ;
     RECT  63.353 8.592 64.692 8.616 ;
     RECT  63.353 8.616 64.716 8.688 ;
     RECT  63.353 8.688 64.692 8.712 ;
     RECT  63.353 8.712 64.716 8.784 ;
     RECT  63.353 8.784 64.692 8.808 ;
     RECT  63.353 8.808 64.716 8.88 ;
     RECT  63.353 8.88 64.692 8.904 ;
     RECT  63.353 8.904 64.716 8.976 ;
     RECT  63.353 8.976 64.692 9 ;
     RECT  63.353 9 64.716 9.072 ;
     RECT  63.353 9.072 64.692 9.096 ;
     RECT  63.353 9.096 64.716 9.168 ;
     RECT  63.353 9.168 64.692 9.192 ;
     RECT  63.353 9.192 64.716 9.264 ;
     RECT  63.353 9.264 64.692 9.288 ;
     RECT  63.353 9.288 64.716 9.36 ;
     RECT  63.353 9.36 64.692 9.384 ;
     RECT  63.353 9.384 64.716 9.456 ;
     RECT  63.353 9.456 64.692 9.48 ;
     RECT  63.353 9.48 64.716 9.552 ;
     RECT  63.353 9.552 64.692 9.576 ;
     RECT  63.353 9.576 64.716 9.648 ;
     RECT  63.353 9.648 64.692 9.672 ;
     RECT  63.353 9.672 64.716 9.744 ;
     RECT  63.353 9.744 64.692 9.768 ;
     RECT  63.353 9.768 64.716 9.84 ;
     RECT  63.353 9.84 64.692 9.864 ;
     RECT  63.353 9.864 64.716 9.936 ;
     RECT  63.353 9.936 64.692 9.96 ;
     RECT  63.353 9.96 64.716 10.032 ;
     RECT  63.353 10.032 64.692 10.056 ;
     RECT  63.353 10.056 64.716 10.128 ;
     RECT  63.353 10.128 64.692 10.152 ;
     RECT  63.353 10.152 64.716 10.224 ;
     RECT  63.353 10.224 64.692 10.248 ;
     RECT  63.353 10.248 64.716 10.32 ;
     RECT  63.353 10.32 64.692 10.344 ;
     RECT  63.353 10.344 64.716 10.416 ;
     RECT  63.353 10.416 64.692 10.44 ;
     RECT  63.353 10.44 64.716 10.512 ;
     RECT  63.353 10.512 64.692 10.536 ;
     RECT  63.353 10.536 64.716 10.608 ;
     RECT  63.353 10.608 64.692 10.632 ;
     RECT  63.353 10.632 64.716 10.704 ;
     RECT  63.353 10.704 64.692 10.728 ;
     RECT  63.353 10.728 64.716 10.8 ;
     RECT  63.353 10.8 64.692 10.824 ;
     RECT  63.353 10.824 64.716 10.896 ;
     RECT  63.353 10.896 64.692 10.92 ;
     RECT  63.353 10.92 64.716 10.992 ;
     RECT  63.353 10.992 64.692 11.016 ;
     RECT  63.353 11.016 64.716 11.088 ;
     RECT  63.353 11.088 64.692 11.112 ;
     RECT  63.353 11.112 64.716 11.184 ;
     RECT  63.353 11.184 64.692 11.208 ;
     RECT  63.353 11.208 64.716 11.28 ;
     RECT  63.353 11.28 64.692 11.304 ;
     RECT  63.353 11.304 64.716 11.376 ;
     RECT  63.353 11.376 64.692 11.4 ;
     RECT  63.353 11.4 64.716 11.472 ;
     RECT  63.353 11.472 64.692 11.496 ;
     RECT  63.353 11.496 64.716 11.568 ;
     RECT  63.353 11.568 64.692 11.592 ;
     RECT  63.353 11.592 64.716 11.664 ;
     RECT  63.353 11.664 64.692 11.688 ;
     RECT  63.353 11.688 64.716 11.76 ;
     RECT  63.353 11.76 64.692 11.784 ;
     RECT  63.353 11.784 64.716 11.856 ;
     RECT  63.353 11.856 64.692 11.88 ;
     RECT  63.353 11.88 64.716 11.952 ;
     RECT  63.353 11.952 64.692 11.976 ;
     RECT  63.353 11.976 64.716 12.048 ;
     RECT  63.353 12.048 64.692 12.072 ;
     RECT  63.353 12.072 64.716 12.144 ;
     RECT  63.353 12.144 64.692 12.168 ;
     RECT  63.353 12.168 64.716 12.24 ;
     RECT  63.353 12.24 64.692 12.264 ;
     RECT  63.353 12.264 64.716 12.336 ;
     RECT  63.353 12.336 64.692 12.36 ;
     RECT  63.353 12.36 64.716 12.432 ;
     RECT  63.353 12.432 64.692 12.456 ;
     RECT  63.353 12.456 64.716 12.528 ;
     RECT  63.353 12.528 64.692 12.552 ;
     RECT  63.353 12.552 64.716 12.624 ;
     RECT  63.353 12.624 64.692 12.648 ;
     RECT  63.353 12.648 64.716 12.72 ;
     RECT  63.353 12.72 64.692 12.744 ;
     RECT  63.353 12.744 64.716 12.816 ;
     RECT  63.353 12.816 64.692 12.84 ;
     RECT  63.353 12.84 64.716 12.912 ;
     RECT  63.353 12.912 64.692 12.936 ;
     RECT  63.853 19.92 64.692 19.944 ;
     RECT  63.853 19.944 64.716 20.016 ;
     RECT  63.853 20.016 64.692 20.04 ;
     RECT  63.853 20.04 64.716 20.112 ;
     RECT  63.853 20.112 64.692 20.136 ;
     RECT  63.853 20.136 64.716 20.208 ;
     RECT  63.853 20.208 64.692 20.232 ;
     RECT  63.853 20.232 64.716 20.304 ;
     RECT  63.853 20.304 64.692 20.328 ;
     RECT  63.853 20.328 64.716 20.4 ;
     RECT  63.853 20.4 64.692 20.424 ;
     RECT  63.853 20.424 64.716 20.496 ;
     RECT  63.853 20.496 64.692 20.52 ;
     RECT  63.853 20.52 64.716 20.592 ;
     RECT  63.853 20.592 64.692 20.616 ;
     RECT  63.853 20.616 64.716 20.688 ;
     RECT  63.853 20.688 64.692 20.712 ;
     RECT  63.853 20.712 64.716 20.784 ;
     RECT  63.853 20.784 64.692 20.808 ;
     RECT  63.853 20.808 64.716 20.88 ;
     RECT  63.853 20.88 64.692 20.904 ;
     RECT  63.853 20.904 64.716 20.976 ;
     RECT  63.853 20.976 64.692 21 ;
     RECT  63.853 21 64.716 21.072 ;
     RECT  63.853 21.072 64.692 21.096 ;
     RECT  63.853 21.096 64.716 21.168 ;
     RECT  63.853 21.168 64.692 21.192 ;
     RECT  63.853 21.192 64.716 21.264 ;
     RECT  63.853 21.264 64.692 21.288 ;
     RECT  63.853 21.288 64.716 21.36 ;
     RECT  63.853 21.36 64.692 21.384 ;
     RECT  63.853 21.384 64.716 21.456 ;
     RECT  63.853 21.456 64.692 21.48 ;
     RECT  63.853 21.48 64.716 21.552 ;
     RECT  63.853 21.552 64.692 21.576 ;
     RECT  63.853 21.576 64.716 21.648 ;
     RECT  63.853 21.648 64.692 21.672 ;
     RECT  63.853 21.672 64.716 21.744 ;
     RECT  63.853 21.744 64.692 21.768 ;
     RECT  63.853 21.768 64.716 21.84 ;
     RECT  63.853 21.84 64.692 21.864 ;
     RECT  63.853 21.864 64.716 21.936 ;
     RECT  63.853 21.936 64.692 21.96 ;
     RECT  63.853 21.96 64.716 22.032 ;
     RECT  63.853 22.032 64.692 22.056 ;
     RECT  63.853 22.056 64.716 22.128 ;
     RECT  63.853 22.128 64.692 22.152 ;
     RECT  63.853 22.152 64.716 22.224 ;
     RECT  63.853 22.224 64.692 22.248 ;
     RECT  63.853 22.248 64.716 22.32 ;
     RECT  63.853 22.32 64.692 22.344 ;
     RECT  63.853 22.344 64.716 22.416 ;
     RECT  63.853 22.416 64.692 22.44 ;
     RECT  63.853 22.44 64.716 22.512 ;
     RECT  63.853 22.512 64.692 22.536 ;
     RECT  63.853 22.536 64.716 22.608 ;
     RECT  63.853 22.608 64.692 22.632 ;
     RECT  63.853 22.632 64.716 22.704 ;
     RECT  63.853 22.704 64.692 22.728 ;
     RECT  63.853 22.728 64.716 22.8 ;
     RECT  63.853 22.8 64.692 22.824 ;
     RECT  63.853 22.824 64.716 22.896 ;
     RECT  63.853 22.896 64.692 22.92 ;
     RECT  63.853 22.92 64.716 22.992 ;
     RECT  63.853 22.992 64.692 23.016 ;
     RECT  63.853 23.016 64.716 23.088 ;
     RECT  63.853 23.088 64.692 23.112 ;
     RECT  63.853 23.112 64.716 23.184 ;
     RECT  63.853 23.184 64.692 23.208 ;
     RECT  63.853 23.208 64.716 23.28 ;
     RECT  63.853 23.28 64.692 23.304 ;
     RECT  63.853 23.304 64.716 23.376 ;
     RECT  63.853 23.376 64.692 23.4 ;
     RECT  63.853 23.4 64.716 23.472 ;
     RECT  63.853 23.472 64.692 23.496 ;
     RECT  63.853 23.496 64.716 23.568 ;
     RECT  63.853 23.568 64.692 23.592 ;
     RECT  63.853 23.592 64.716 23.664 ;
     RECT  63.853 23.664 64.692 23.688 ;
     RECT  63.853 23.688 64.716 23.76 ;
     RECT  63.853 23.76 64.692 23.784 ;
     RECT  63.853 23.784 64.716 23.856 ;
     RECT  63.853 23.856 64.692 23.88 ;
     RECT  63.853 23.88 64.716 23.952 ;
     RECT  63.853 23.952 64.692 23.976 ;
     RECT  63.853 23.976 64.716 24.048 ;
     RECT  63.853 24.048 64.692 24.072 ;
     RECT  63.853 24.072 64.716 24.144 ;
     RECT  63.853 24.144 64.692 24.168 ;
     RECT  63.853 24.168 64.716 24.24 ;
     RECT  63.853 24.24 64.692 24.264 ;
     RECT  63.853 24.264 64.716 24.336 ;
     RECT  63.853 24.336 64.692 24.36 ;
     RECT  63.853 24.36 64.716 24.432 ;
     RECT  63.853 24.432 64.692 24.456 ;
     RECT  63.853 24.456 64.716 24.528 ;
     RECT  63.853 24.528 64.692 24.552 ;
     RECT  63.853 24.552 64.716 24.624 ;
     RECT  63.853 24.624 64.692 24.648 ;
     RECT  63.853 24.648 64.716 24.72 ;
     RECT  63.853 24.72 64.692 24.744 ;
     RECT  63.853 24.744 64.716 24.816 ;
     RECT  63.853 24.816 64.692 24.84 ;
     RECT  63.853 24.84 64.716 24.912 ;
     RECT  63.853 24.912 64.692 24.936 ;
     RECT  63.853 24.936 64.716 25.008 ;
     RECT  63.853 25.008 64.692 25.032 ;
     RECT  63.853 25.032 64.716 25.104 ;
     RECT  63.853 25.104 64.692 25.128 ;
     RECT  63.853 25.128 64.716 25.2 ;
     RECT  63.853 25.2 64.692 25.224 ;
     RECT  63.853 25.224 64.716 25.296 ;
     RECT  63.853 25.296 64.692 25.32 ;
     RECT  63.853 25.32 64.716 25.392 ;
     RECT  63.853 25.392 64.692 25.416 ;
     RECT  63.853 25.416 64.716 25.488 ;
     RECT  63.853 25.488 64.692 25.512 ;
     RECT  63.853 25.512 64.716 25.584 ;
     RECT  63.853 25.584 64.692 25.608 ;
     RECT  63.853 25.608 64.716 25.68 ;
     RECT  63.853 25.68 64.692 25.704 ;
     RECT  63.853 25.704 64.716 25.776 ;
     RECT  63.853 25.776 64.692 25.8 ;
     RECT  63.853 25.8 64.716 25.872 ;
     RECT  63.853 25.872 64.692 25.896 ;
     RECT  63.853 25.896 64.716 25.968 ;
     RECT  63.853 25.968 64.692 25.992 ;
     RECT  64.716 8.544 64.757 8.592 ;
     RECT  64.716 8.616 64.757 8.688 ;
     RECT  64.716 8.712 64.757 8.784 ;
     RECT  64.716 8.808 64.757 8.88 ;
     RECT  64.716 8.904 64.757 8.976 ;
     RECT  64.716 9 64.757 9.072 ;
     RECT  64.716 9.096 64.757 9.168 ;
     RECT  64.716 9.192 64.757 9.24 ;
     RECT  64.716 11.808 64.757 11.832 ;
     RECT  62.104 16.608 64.757 16.632 ;
     RECT  64.716 21.792 64.757 21.816 ;
    LAYER M5 ;
     RECT  2.4 2.137 2.52 2.151 ;
     RECT  5.1 2.137 5.22 2.151 ;
     RECT  7.8 2.137 7.92 2.151 ;
     RECT  10.5 2.137 10.62 2.151 ;
     RECT  13.2 2.137 13.32 2.151 ;
     RECT  15.9 2.137 16.02 2.151 ;
     RECT  18.6 2.137 18.72 2.151 ;
     RECT  21.3 2.137 21.42 2.151 ;
     RECT  24 2.137 24.12 2.151 ;
     RECT  26.7 2.137 26.82 2.151 ;
     RECT  29.4 2.137 29.52 2.151 ;
     RECT  32.1 2.137 32.22 2.151 ;
     RECT  34.8 2.137 34.92 2.151 ;
     RECT  37.5 2.137 37.62 2.151 ;
     RECT  40.2 2.137 40.32 2.151 ;
     RECT  42.9 2.137 43.02 2.151 ;
     RECT  45.6 2.137 45.72 2.151 ;
     RECT  48.3 2.137 48.42 2.151 ;
     RECT  51 2.137 51.12 2.151 ;
     RECT  53.7 2.137 53.82 2.151 ;
     RECT  56.4 2.137 56.52 2.151 ;
     RECT  59.1 2.137 59.22 2.151 ;
     RECT  61.8 2.137 61.92 2.151 ;
     RECT  7.8 2.151 8.112 2.821 ;
     RECT  24 2.151 24.312 2.821 ;
     RECT  18.6 2.151 18.912 2.869 ;
     RECT  20.112 2.629 20.136 3.109 ;
     RECT  21.3 2.151 21.612 3.109 ;
     RECT  20.112 3.109 22.296 3.155 ;
     RECT  15.9 2.151 16.212 3.541 ;
     RECT  24 2.821 24.504 3.733 ;
     RECT  17.664 2.869 18.912 3.779 ;
     RECT  20.496 3.155 22.296 4.115 ;
     RECT  5.1 2.151 5.412 4.213 ;
     RECT  26.7 2.151 27.012 4.213 ;
     RECT  24 3.733 25.08 4.259 ;
     RECT  15.024 3.541 16.212 4.357 ;
     RECT  4.896 4.213 5.412 4.453 ;
     RECT  7.8 2.821 9.096 4.453 ;
     RECT  4.896 4.453 5.784 4.501 ;
     RECT  34.8 2.151 35.112 4.501 ;
     RECT  20.496 4.115 21.612 4.643 ;
     RECT  15.024 4.357 16.776 4.787 ;
     RECT  2.4 2.151 2.712 5.077 ;
     RECT  4.512 4.501 5.784 5.125 ;
     RECT  6.816 4.453 9.192 5.125 ;
     RECT  18.6 3.779 18.912 5.125 ;
     RECT  32.1 2.151 32.412 5.125 ;
     RECT  4.512 5.125 9.192 5.173 ;
     RECT  4.512 5.173 9.24 5.267 ;
     RECT  12.096 3.397 12.12 5.267 ;
     RECT  29.4 2.151 29.712 5.365 ;
     RECT  37.5 2.151 37.812 5.365 ;
     RECT  15.9 4.787 16.776 5.555 ;
     RECT  34.416 4.501 35.112 5.747 ;
     RECT  37.5 5.365 38.568 5.749 ;
     RECT  32.1 5.125 32.52 5.893 ;
     RECT  26.7 4.213 27.72 5.939 ;
     RECT  4.512 5.267 6.264 5.989 ;
     RECT  2.4 5.077 3.24 6.229 ;
     RECT  4.272 5.989 6.264 6.229 ;
     RECT  7.8 5.267 9.24 6.229 ;
     RECT  26.7 5.939 27.012 6.229 ;
     RECT  24 4.259 24.984 6.323 ;
     RECT  29.4 5.365 30.552 6.323 ;
     RECT  37.392 5.749 38.568 6.611 ;
     RECT  15.9 5.555 16.344 6.659 ;
     RECT  18.6 5.125 19.752 6.661 ;
     RECT  7.8 6.229 9.528 6.805 ;
     RECT  10.5 2.151 10.812 6.805 ;
     RECT  34.8 5.747 35.112 6.805 ;
     RECT  37.5 6.611 38.568 6.851 ;
     RECT  2.4 6.229 6.264 6.899 ;
     RECT  2.4 6.899 2.808 7.043 ;
     RECT  32.1 5.893 33.096 7.043 ;
     RECT  34.8 6.805 35.64 7.139 ;
     RECT  7.8 6.805 10.812 7.237 ;
     RECT  7.44 7.237 10.812 7.475 ;
     RECT  7.44 7.475 9.528 7.619 ;
     RECT  24 6.323 24.552 7.619 ;
     RECT  0.192 7.381 0.216 7.669 ;
     RECT  4.512 6.899 6.264 7.861 ;
     RECT  3.936 7.861 6.264 7.909 ;
     RECT  7.44 7.619 8.52 7.909 ;
     RECT  0.144 7.669 0.216 7.955 ;
     RECT  3.936 7.909 8.52 8.003 ;
     RECT  0.192 7.955 0.216 8.147 ;
     RECT  18.6 6.661 19.992 8.435 ;
     RECT  34.8 7.139 35.256 8.533 ;
     RECT  11.952 7.621 11.976 8.579 ;
     RECT  6.912 8.003 8.52 9.011 ;
     RECT  6.912 9.011 8.112 9.013 ;
     RECT  9.504 7.619 9.528 9.061 ;
     RECT  10.5 7.475 10.812 9.061 ;
     RECT  26.448 6.229 27.012 9.061 ;
     RECT  9.504 9.061 10.812 9.107 ;
     RECT  15.9 6.659 16.212 9.109 ;
     RECT  34.8 8.533 36.072 9.155 ;
     RECT  3.936 8.003 5.736 9.251 ;
     RECT  4.032 9.251 5.736 9.299 ;
     RECT  26.448 9.061 27.912 9.445 ;
     RECT  13.2 2.151 13.512 9.589 ;
     RECT  37.5 6.851 37.812 9.637 ;
     RECT  15.9 9.109 17.16 9.731 ;
     RECT  0.144 8.917 0.168 9.877 ;
     RECT  0.144 9.877 0.264 10.019 ;
     RECT  0.24 10.019 0.264 10.163 ;
     RECT  9.648 9.107 10.812 10.213 ;
     RECT  37.392 9.637 37.812 10.213 ;
     RECT  4.032 9.299 4.056 10.261 ;
     RECT  5.1 9.299 5.736 10.261 ;
     RECT  4.032 10.261 5.736 10.307 ;
     RECT  6.816 9.013 8.112 10.307 ;
     RECT  13.056 9.589 13.512 10.307 ;
     RECT  25.68 9.445 27.912 10.307 ;
     RECT  7.68 10.307 8.112 10.355 ;
     RECT  24 7.619 24.312 10.597 ;
     RECT  37.392 10.213 38.232 10.691 ;
     RECT  7.8 10.355 8.112 10.789 ;
     RECT  9.552 10.213 10.812 10.789 ;
     RECT  26.544 10.307 27.912 10.883 ;
     RECT  24 10.597 24.408 11.267 ;
     RECT  18.6 8.435 19.08 11.269 ;
     RECT  4.896 10.307 5.736 11.365 ;
     RECT  37.5 10.691 38.232 11.651 ;
     RECT  4.512 11.365 5.736 11.749 ;
     RECT  13.2 10.307 13.512 11.941 ;
     RECT  18.6 11.269 19.176 11.941 ;
     RECT  20.208 10.933 20.232 11.941 ;
     RECT  4.512 11.749 5.832 11.989 ;
     RECT  15.9 9.731 16.584 12.035 ;
     RECT  30.768 10.165 30.792 12.035 ;
     RECT  18.6 11.941 20.232 12.179 ;
     RECT  4.032 11.989 5.832 12.275 ;
     RECT  21.3 4.643 21.612 12.517 ;
     RECT  4.032 12.275 4.056 12.755 ;
     RECT  32.1 7.043 32.412 12.949 ;
     RECT  7.8 10.789 10.812 12.995 ;
     RECT  34.8 9.155 35.256 13.045 ;
     RECT  5.1 12.275 5.832 13.139 ;
     RECT  13.056 11.941 13.512 13.139 ;
     RECT  18.6 12.179 19.416 13.139 ;
     RECT  34.8 13.045 35.784 13.187 ;
     RECT  21.3 12.517 22.2 13.331 ;
     RECT  26.544 10.883 27.288 13.667 ;
     RECT  9.36 12.995 10.812 13.763 ;
     RECT  31.92 12.949 32.412 13.957 ;
     RECT  24 11.267 24.312 14.197 ;
     RECT  7.8 12.995 8.112 14.533 ;
     RECT  13.2 13.139 13.512 14.629 ;
     RECT  23.136 14.197 24.312 14.867 ;
     RECT  31.92 13.957 33 14.867 ;
     RECT  26.544 13.667 27.144 14.963 ;
     RECT  18.6 13.139 19.176 15.205 ;
     RECT  32.1 14.867 33 15.347 ;
     RECT  36.432 13.765 36.456 15.395 ;
     RECT  5.1 13.139 5.64 15.685 ;
     RECT  7.2 14.533 8.112 15.685 ;
     RECT  5.1 15.685 8.112 15.731 ;
     RECT  10.5 13.763 10.812 15.733 ;
     RECT  26.544 14.963 27.012 15.779 ;
     RECT  10.5 15.733 10.92 15.781 ;
     RECT  10.5 15.781 11.784 15.829 ;
     RECT  17.568 15.349 17.592 16.499 ;
     RECT  10.368 15.829 11.784 16.501 ;
     RECT  13.104 14.629 13.512 16.501 ;
     RECT  18.6 15.205 19.656 16.501 ;
     RECT  34.8 13.187 35.256 16.549 ;
     RECT  15.9 12.035 16.212 16.693 ;
     RECT  5.1 15.731 5.412 16.885 ;
     RECT  6.576 15.731 8.112 16.981 ;
     RECT  9.36 13.763 9.384 16.981 ;
     RECT  5.1 16.885 5.544 17.029 ;
     RECT  24 14.867 24.312 17.077 ;
     RECT  4.512 17.029 5.544 17.125 ;
     RECT  6.576 16.981 9.384 17.125 ;
     RECT  18.6 16.501 20.328 17.461 ;
     RECT  21.3 13.331 21.612 17.461 ;
     RECT  24 17.077 24.888 17.651 ;
     RECT  15.9 16.693 16.488 17.653 ;
     RECT  4.512 17.125 9.384 17.699 ;
     RECT  18.6 17.461 21.612 18.035 ;
     RECT  37.5 11.651 37.812 18.133 ;
     RECT  15.9 17.653 16.536 18.181 ;
     RECT  29.4 6.323 29.712 18.181 ;
     RECT  34.8 16.549 35.88 18.227 ;
     RECT  5.1 17.699 9.384 18.275 ;
     RECT  15.408 18.181 16.536 18.275 ;
     RECT  10.368 16.501 13.512 18.325 ;
     RECT  15.408 18.275 16.488 18.371 ;
     RECT  18.6 18.035 20.136 18.467 ;
     RECT  17.568 18.181 17.592 18.515 ;
     RECT  26.7 15.779 27.012 18.661 ;
     RECT  28.176 15.733 28.2 18.661 ;
     RECT  10.368 18.325 13.608 18.755 ;
     RECT  37.5 18.133 38.04 18.755 ;
     RECT  5.1 18.275 8.112 18.757 ;
     RECT  10.368 18.755 13.512 18.803 ;
     RECT  40.2 2.151 40.512 18.805 ;
     RECT  10.5 18.803 13.512 18.851 ;
     RECT  26.7 18.661 28.2 19.237 ;
     RECT  29.4 18.181 29.832 19.237 ;
     RECT  34.8 18.227 35.352 19.237 ;
     RECT  2.4 7.043 2.712 19.285 ;
     RECT  24 17.651 24.312 19.381 ;
     RECT  21.12 18.035 21.612 19.427 ;
     RECT  26.7 19.237 29.832 19.427 ;
     RECT  0.144 18.997 0.168 19.667 ;
     RECT  4.848 18.757 8.112 19.669 ;
     RECT  42.9 2.151 43.212 19.813 ;
     RECT  34.8 19.237 35.4 19.909 ;
     RECT  4.512 19.669 8.112 20.003 ;
     RECT  15.408 18.371 16.212 20.003 ;
     RECT  24 19.381 25.224 20.003 ;
     RECT  4.512 20.003 6.12 20.051 ;
     RECT  2.4 19.285 2.904 20.053 ;
     RECT  4.512 20.051 5.412 20.053 ;
     RECT  28.176 19.427 29.832 20.195 ;
     RECT  7.104 20.003 8.112 20.293 ;
     RECT  24 20.003 24.312 20.293 ;
     RECT  33.792 18.421 33.816 20.339 ;
     RECT  37.5 18.755 37.812 20.485 ;
     RECT  42.384 19.813 43.212 20.627 ;
     RECT  40.2 18.805 40.632 20.773 ;
     RECT  15.9 20.003 16.212 20.965 ;
     RECT  34.8 19.909 35.688 21.061 ;
     RECT  2.4 20.053 5.412 21.155 ;
     RECT  7.104 20.293 8.232 21.203 ;
     RECT  37.5 20.485 38.232 21.205 ;
     RECT  2.4 21.155 3.432 21.251 ;
     RECT  4.512 21.155 5.412 21.251 ;
     RECT  36.816 21.205 38.232 21.347 ;
     RECT  2.4 21.251 2.712 21.493 ;
     RECT  32.1 15.347 32.412 21.637 ;
     RECT  2.304 21.493 2.712 21.683 ;
     RECT  23.616 20.293 24.312 21.683 ;
     RECT  37.5 21.347 38.232 21.683 ;
     RECT  7.8 21.203 8.232 22.165 ;
     RECT  9.36 18.275 9.384 22.165 ;
     RECT  34.08 21.061 35.688 22.165 ;
     RECT  10.5 18.851 11.784 22.213 ;
     RECT  33.552 22.165 35.688 22.499 ;
     RECT  2.4 21.683 2.712 22.741 ;
     RECT  34.8 22.499 35.688 22.835 ;
     RECT  31.248 21.637 32.412 23.027 ;
     RECT  4.992 21.251 5.412 23.123 ;
     RECT  37.5 21.683 37.812 23.173 ;
     RECT  7.8 22.165 9.384 23.269 ;
     RECT  10.368 22.213 11.784 23.269 ;
     RECT  2.4 22.741 2.856 23.315 ;
     RECT  23.808 21.683 24.312 23.315 ;
     RECT  15.552 20.965 16.212 23.317 ;
     RECT  25.632 22.501 25.656 23.317 ;
     RECT  26.7 19.427 27.012 23.317 ;
     RECT  25.632 23.317 27.012 23.411 ;
     RECT  15.552 23.317 16.344 23.555 ;
     RECT  33.552 22.499 33.576 23.555 ;
     RECT  0.144 22.789 0.168 23.603 ;
     RECT  40.2 20.773 40.728 23.747 ;
     RECT  7.8 23.269 11.784 23.987 ;
     RECT  37.056 23.173 37.812 24.277 ;
     RECT  28.176 20.195 29.712 24.323 ;
     RECT  13.2 18.851 13.512 24.469 ;
     RECT  37.056 24.277 38.136 24.515 ;
     RECT  32.1 23.027 32.412 24.517 ;
     RECT  7.8 23.987 9.384 24.611 ;
     RECT  40.2 23.747 40.632 24.659 ;
     RECT  21.3 19.427 21.612 24.661 ;
     RECT  26.064 23.411 27.012 24.709 ;
     RECT  28.992 24.323 29.712 24.755 ;
     RECT  21.168 24.661 21.612 25.043 ;
     RECT  7.8 24.611 9.096 25.045 ;
     RECT  32.1 24.517 33.192 25.139 ;
     RECT  10.368 23.987 11.784 25.187 ;
     RECT  7.632 25.045 9.096 25.715 ;
     RECT  25.68 24.709 27.012 25.715 ;
     RECT  37.5 24.515 38.136 25.715 ;
     RECT  18.6 18.467 19.656 25.717 ;
     RECT  15.9 23.555 16.344 26.149 ;
     RECT  7.632 25.715 8.808 26.243 ;
     RECT  7.632 26.243 8.112 26.291 ;
     RECT  13.2 24.469 13.656 26.581 ;
     RECT  15.9 26.149 17.16 26.773 ;
     RECT  15.12 26.773 17.16 26.819 ;
     RECT  18.48 25.717 19.656 26.819 ;
     RECT  15.12 26.819 16.212 26.915 ;
     RECT  13.2 26.581 14.136 27.347 ;
     RECT  25.68 25.715 25.704 27.683 ;
     RECT  2.4 23.315 2.712 27.819 ;
     RECT  5.1 23.123 5.412 27.819 ;
     RECT  7.8 26.291 8.112 27.819 ;
     RECT  10.5 25.187 11.784 27.819 ;
     RECT  13.2 27.347 13.512 27.819 ;
     RECT  15.9 26.915 16.212 27.819 ;
     RECT  18.6 26.819 19.656 27.819 ;
     RECT  21.3 25.043 21.612 27.819 ;
     RECT  24 23.315 24.312 27.819 ;
     RECT  26.7 25.715 27.012 27.819 ;
     RECT  29.4 24.755 29.712 27.819 ;
     RECT  32.1 25.139 32.412 27.819 ;
     RECT  34.8 22.835 35.112 27.819 ;
     RECT  37.5 25.715 37.812 27.819 ;
     RECT  40.2 24.659 40.512 27.819 ;
     RECT  42.9 20.627 43.212 27.819 ;
     RECT  45.6 2.151 45.912 27.819 ;
     RECT  48.3 2.151 48.612 27.819 ;
     RECT  51 2.151 51.312 27.819 ;
     RECT  53.7 2.151 54.012 27.819 ;
     RECT  56.4 2.151 56.712 27.819 ;
     RECT  59.1 2.151 59.412 27.819 ;
     RECT  61.8 2.151 62.112 27.819 ;
     RECT  2.592 27.819 2.712 27.833 ;
     RECT  5.292 27.819 5.412 27.833 ;
     RECT  7.992 27.819 8.112 27.833 ;
     RECT  10.692 27.819 11.784 27.833 ;
     RECT  13.392 27.819 13.512 27.833 ;
     RECT  16.092 27.819 16.212 27.833 ;
     RECT  18.792 27.819 19.656 27.833 ;
     RECT  21.492 27.819 21.612 27.833 ;
     RECT  24.192 27.819 24.312 27.833 ;
     RECT  26.892 27.819 27.012 27.833 ;
     RECT  29.592 27.819 29.712 27.833 ;
     RECT  32.292 27.819 32.412 27.833 ;
     RECT  34.992 27.819 35.112 27.833 ;
     RECT  37.692 27.819 37.812 27.833 ;
     RECT  40.392 27.819 40.512 27.833 ;
     RECT  43.092 27.819 43.212 27.833 ;
     RECT  45.792 27.819 45.912 27.833 ;
     RECT  48.492 27.819 48.612 27.833 ;
     RECT  51.192 27.819 51.312 27.833 ;
     RECT  53.892 27.819 54.012 27.833 ;
     RECT  56.592 27.819 56.712 27.833 ;
     RECT  59.292 27.819 59.412 27.833 ;
     RECT  61.992 27.819 62.112 27.833 ;
     RECT  11.76 27.833 11.784 29.699 ;
     RECT  19.632 27.833 19.656 30.179 ;
     RECT  18.912 2.629 20.112 3.155 ;
     RECT  20.136 2.629 21.3 3.109 ;
     RECT  9.096 2.821 10.5 4.453 ;
     RECT  16.212 2.869 17.664 3.779 ;
     RECT  10.812 3.397 12.096 5.267 ;
     RECT  12.12 3.397 13.2 5.267 ;
     RECT  13.512 3.541 15.024 4.787 ;
     RECT  16.212 3.779 16.776 4.357 ;
     RECT  5.784 4.453 6.816 5.125 ;
     RECT  9.192 4.453 10.5 5.173 ;
     RECT  3.24 5.077 4.512 5.989 ;
     RECT  9.24 5.173 10.5 6.229 ;
     RECT  3.24 5.989 4.272 6.229 ;
     RECT  9.528 6.229 10.5 6.805 ;
     RECT  24.984 6.229 26.448 6.323 ;
     RECT  19.992 6.661 21.3 8.435 ;
     RECT  2.808 6.899 4.512 7.043 ;
     RECT  2.712 7.043 4.512 7.861 ;
     RECT  35.256 7.139 35.64 8.533 ;
     RECT  6.264 7.237 7.44 7.909 ;
     RECT  9.528 7.475 10.5 9.061 ;
     RECT  8.52 7.619 9.504 9.011 ;
     RECT  10.812 7.621 11.952 8.579 ;
     RECT  11.976 7.621 13.2 8.579 ;
     RECT  2.712 7.861 3.936 9.251 ;
     RECT  0.144 7.955 0.192 8.147 ;
     RECT  5.736 8.003 6.912 9.013 ;
     RECT  0.144 8.147 0.168 8.917 ;
     RECT  36.072 8.533 37.5 9.155 ;
     RECT  13.056 8.579 13.2 9.589 ;
     RECT  8.112 9.011 9.504 9.107 ;
     RECT  5.736 9.013 6.816 10.307 ;
     RECT  27.912 9.061 29.4 10.883 ;
     RECT  8.112 9.107 9.648 10.213 ;
     RECT  17.16 9.109 18.6 9.731 ;
     RECT  37.392 9.155 37.5 9.637 ;
     RECT  2.712 9.251 4.032 10.307 ;
     RECT  4.056 9.299 5.1 10.261 ;
     RECT  24.312 9.445 25.68 10.307 ;
     RECT  29.712 10.165 30.768 12.035 ;
     RECT  30.792 10.165 32.1 12.035 ;
     RECT  8.112 10.213 9.552 10.789 ;
     RECT  4.512 10.307 4.896 11.365 ;
     RECT  5.736 10.307 5.832 11.749 ;
     RECT  24.312 10.307 24.408 10.597 ;
     RECT  19.08 10.933 20.208 11.269 ;
     RECT  20.232 10.933 21.3 12.179 ;
     RECT  19.176 11.269 20.208 11.941 ;
     RECT  2.712 11.989 4.032 12.755 ;
     RECT  31.92 12.035 32.1 12.949 ;
     RECT  4.056 12.275 5.1 12.755 ;
     RECT  8.112 12.995 9.36 16.981 ;
     RECT  13.104 13.139 13.2 14.629 ;
     RECT  35.256 13.187 35.784 13.765 ;
     RECT  21.612 13.331 22.2 14.197 ;
     RECT  9.384 13.763 10.5 15.829 ;
     RECT  35.256 13.765 36.432 15.395 ;
     RECT  36.456 13.765 37.5 15.395 ;
     RECT  21.612 14.197 23.136 14.867 ;
     RECT  27.012 14.963 27.144 15.733 ;
     RECT  16.212 15.349 17.568 16.499 ;
     RECT  17.592 15.349 18.6 16.499 ;
     RECT  35.256 15.395 35.88 16.549 ;
     RECT  5.412 15.731 6.576 16.885 ;
     RECT  27.012 15.733 28.176 18.661 ;
     RECT  28.2 15.733 29.4 19.237 ;
     RECT  11.784 15.781 13.104 16.501 ;
     RECT  9.384 15.829 10.368 18.803 ;
     RECT  16.212 16.499 16.536 16.693 ;
     RECT  20.328 16.501 21.3 17.461 ;
     RECT  16.488 16.693 16.536 17.653 ;
     RECT  5.544 16.885 6.576 17.125 ;
     RECT  4.848 17.699 5.1 18.757 ;
     RECT  20.136 18.035 21.12 18.467 ;
     RECT  16.536 18.181 17.568 18.275 ;
     RECT  17.592 18.181 18.6 18.515 ;
     RECT  35.352 18.227 35.4 19.237 ;
     RECT  8.112 18.275 9.36 20.293 ;
     RECT  16.488 18.275 17.568 18.371 ;
     RECT  16.212 18.371 17.568 18.515 ;
     RECT  32.412 18.421 33.792 20.339 ;
     RECT  33.816 18.421 34.8 20.339 ;
     RECT  19.656 18.467 21.12 19.427 ;
     RECT  9.384 18.803 10.5 22.213 ;
     RECT  11.784 18.851 13.2 27.819 ;
     RECT  25.224 19.381 26.7 20.003 ;
     RECT  27.012 19.427 28.176 24.323 ;
     RECT  6.12 20.003 7.104 20.051 ;
     RECT  15.552 20.003 15.9 20.965 ;
     RECT  8.232 20.293 9.36 22.165 ;
     RECT  34.08 20.339 34.8 21.061 ;
     RECT  3.432 21.155 4.512 21.251 ;
     RECT  35.688 21.205 36.816 21.347 ;
     RECT  2.712 21.251 2.856 22.741 ;
     RECT  32.412 22.165 33.552 23.555 ;
     RECT  9.384 22.213 10.368 23.269 ;
     RECT  33.576 22.499 34.8 23.555 ;
     RECT  24.312 22.501 25.632 23.411 ;
     RECT  25.656 22.501 26.7 23.317 ;
     RECT  24.312 23.411 26.064 24.709 ;
     RECT  32.412 23.555 33.192 24.517 ;
     RECT  9.384 23.987 10.368 24.611 ;
     RECT  9.096 24.611 10.368 25.187 ;
     RECT  19.656 24.661 21.168 25.043 ;
     RECT  24.312 24.709 25.68 27.683 ;
     RECT  9.096 25.187 10.5 25.715 ;
     RECT  25.704 25.715 26.7 27.683 ;
     RECT  17.16 26.149 18.48 26.819 ;
     RECT  14.136 26.773 15.12 26.915 ;
  END
END qfd_landh0_128_EW_65x30
END LIBRARY
